PROGRAM Interlock
VAR
	TON_PG21: TON;
	TON_PG22: TOF;
	TON_PG23: TOF;
	MS11_S_TON: TON;
	MS2_S_TON: TON;
	MS12_S_TON: TON;
	BufferN2Press_TON: TON;
	VP1Down_TON: TON;
	DG1_TON: TON;
	OT_RHC_TON: TON;
	BlowerOverLoad_RTrig: R_TRIG;
	HTConc_RTrig: R_TRIG;
	T102Conc_RTrig: R_TRIG;
	
	VAC1_TON: TON;
	VAC1_Bypass: R_TRIG;
	bVAC1_Bypass: BOOL;
	VAC2_TON: TON;
	bVAC2_Bypass: BOOL;
	VAC2_Bypass: R_TRIG;
	VAC3_TON: TON;
	bVAC3_Bypass: BOOL;
	VAC3_Bypass: R_TRIG;
	VAC4_TON: TON;
	bVAC4_Bypass: BOOL;
	VAC4_Bypass: R_TRIG;
	VAC5_TON: TON;
	bVAC5_Bypass: BOOL;
	VAC5_Bypass: R_TRIG;
	AV73_TOF: TOF;
	T_REF_TON: TON;
	FL301_TON: TON;
	
	bRHC_Damper_Open			:BOOL;	// RHC Dapmer in open position
	bRHC_Damper_Close			:BOOL;	// RHC Damper in close position
	bMS2_MS2S_Status_Abnormal	:BOOL;	// MS2和MS2-S状态不一致
	bMS11_MS11S_Status_Abnormal	:BOOL;	// MS11和MS11-S状态不一致
	bMS12_MS12S_Status_Abnormal	:BOOL;	// MS12和MS12-S状态不一致
	bGV_Open					:BOOL;	// Gate valve open status
	bGV_Close					:BOOL;	// Gate valve close status
	bFFUAlarm					:BOOL;	// FFU alarm
	GV_Open_TON: TON;
	GV_Close_TON: TON;
	ATM_Dpr_Cl_TON: TON;
	ATM_Dpr_Op_TON: TON;
	Cycle_Dpr_Op_TON: TON;
	Cycle_Dpr_Cl_TON: TON;
	LSC_Float_Abnormal_TON: TON;
	LSC_HH_TON: TON;
	LSC_H_TON:TON;
	LSC_M_TON: TON;
	LSC_L_TON: TON;
	GasMS_Abnormal_TON :TON;
	T_REF_ET: TIME;
	AV73_ET: TIME;
	GV_Open_ET: TIME;
	GV_Close_ET: TIME;
	BufferN2Press_ET: TIME;
	LSC_Float_Abnormal_ET: TIME;
	TON_PG23_ET: TIME;
	LSC_HH_TON_ET: TIME;
	LSC_H_TON_ET: TIME;
	LSC_M_TON_ET: TIME;
	LSC_L_TON_ET: TIME;
	VP1Down_TON_ET: TIME;
	ATM_Dpr_Op_TON_ET: TIME;
	ATM_Dpr_Cl_TON_ET: TIME;
	Cycle_Dpr_Op_TON_ET: TIME;
	Cycle_Dpr_Cl_TON_ET: TIME;
	MS12_S_TON_ET: TIME;
	MS11_S_TON_ET: TIME;
	MS2_S_TON_ET: TIME;
	FL301_TON_ET: TIME;
	TON_PG22_TON: TIME;
	DG1_TON_ET: TIME;
	GasMS_Abnormal_TON_ET: TIME;
	TON_PG21_ET: TIME;
	OT_RHC_TON_ET: TIME;
	VAC4_TON_ET: TIME;
	VAC1_TON_ET: TIME;
	VAC5_TON_ET: TIME;
	VAC3_TON_ET: TIME;
	VAC2_TON_ET: TIME;
	PG23_TON: TON;
	PG22_TON: TON;
	RHC_Damper_Pos_TON: TON;
	RHC_Damper_Pos_TON_ET: TIME;
	LSC1_Refill_TON: TON;
	LSC1_H_Trig: R_TRIG;
	bLSC1_H_OK: BOOL;
	LSC1_Refill_TON_ET: TIME;
	PS21_TON: TON;
	PS21_TON_ET: TIME;
	VG11_Warning	: dut_UDINT_BOOL ;
	VG11_Error		: dut_UDINT_BOOL ;
	VG13_Warning	: dut_UDINT_BOOL ;
	VG13_Error		: dut_UDINT_BOOL ;
	VG31_Warning	: dut_UDINT_BOOL ;
	VG31_Error		: dut_UDINT_BOOL ;
END_VAR
VAR // added by the converter: edge detectors and wires of the graphical bodies
    _w1, _w2, _w3, _w4, _w5, _w6, _w7, _w8, _w9, _w10, _w11, _w12, _w13, _w14, _w15, _w16, _w17 : BOOL;
    _ft1 : F_TRIG;
END_VAR

//Interlock平时不触发为OFF，触发时为ON并发出报警相关阀无法打开，需要复位后才可进一步操作

INTLK();
Valve_Intlk();
AutoValve_Intlk();
VAC_Condition();
BoatUnload_Intlk();

bRHC_Damper_Open := stEXHI.I303_02 AND stEXHI.I303_04 AND stEXHI.I303_06 AND stEXHI.I303_08 ;
bRHC_Damper_Close:= stEXHI.I303_03 AND stEXHI.I303_05 AND stEXHI.I303_07 AND stEXHI.I303_09 ;

bMS2_MS2S_Status_Abnormal   := stGBI.I202_00 XOR GVL.stPMCtoPLC.MS2_S_gas_box_exhaust_alarm  ;
bMS11_MS11S_Status_Abnormal := stOPI.I600_10 XOR GVL.stPMCtoPLC.MS11_S_gas_box_exhaust_alarm ;
bMS12_MS12S_Status_Abnormal := stOPI.I600_12 XOR GVL.stPMCtoPLC.MS12_S_gas_box_exhaust_alarm ;

bGV_Open	:= stEXHI.I303_13 AND stEXHI.I303_15 ;
bGV_Close	:= stEXHI.I303_12 AND stEXHI.I303_14 ;

VG11_Warning.Data_UDINT := GVL.stPMCtoPLC.VG11_Active_Device_Warning_Details ;
VG11_Error.Data_UDINT	:= GVL.stPMCtoPLC.VG11_Active_Device_Error_Details	 ;

VG13_Warning.Data_UDINT := GVL.stPMCtoPLC.VG13_Active_Device_Warning_Details ;
VG13_Error.Data_UDINT	:= GVL.stPMCtoPLC.VG13_Active_Device_Error_Details	 ;

VG31_Warning.Data_UDINT := GVL.stPMCtoPLC.VG31_Active_Device_Warning_Details ;
VG31_Error.Data_UDINT	:= GVL.stPMCtoPLC.VG31_Active_Device_Error_Details	 ;

//FFU停转状态
bFFUAlarm := 
	( AI.FFU1_1_STATUS = 1 OR AI.FFU1_1_STATUS = 4 ) OR 
	( AI.FFU1_2_STATUS = 1 OR AI.FFU1_2_STATUS = 4 ) OR 
	( AI.FFU1_3_STATUS = 1 OR AI.FFU1_3_STATUS = 4 ) OR 
	( AI.FFU1_4_STATUS = 1 OR AI.FFU1_4_STATUS = 4 ) OR 
	( AI.FFU1_5_STATUS = 1 OR AI.FFU1_5_STATUS = 4 ) OR 
	( AI.FFU1_6_STATUS = 1 OR AI.FFU1_6_STATUS = 4 ) OR 
	( AI.FFU2_1_STATUS = 1 OR AI.FFU2_1_STATUS = 4 ) OR 
	( AI.FFU2_2_STATUS = 1 OR AI.FFU2_2_STATUS = 4 ) OR 
	( AI.FFU2_3_STATUS = 1 OR AI.FFU2_3_STATUS = 4 ) OR 
	( AI.FFU2_4_STATUS = 1 OR AI.FFU2_4_STATUS = 4 ) OR 
	( AI.FFU2_5_STATUS = 1 OR AI.FFU2_5_STATUS = 4 ) OR 
	( AI.FFU2_6_STATUS = 1 OR AI.FFU2_6_STATUS = 4 ) OR 
	( AI.FFU3_1_STATUS = 1 OR AI.FFU3_1_STATUS = 4 ) OR 
	( AI.FFU3_2_STATUS = 1 OR AI.FFU3_2_STATUS = 4 ) OR 
	( AI.FFU3_3_STATUS = 1 OR AI.FFU3_3_STATUS = 4 ) OR 
	( AI.FFU3_4_STATUS = 1 OR AI.FFU3_4_STATUS = 4 ) OR 
	( AI.FFU3_5_STATUS = 1 OR AI.FFU3_5_STATUS = 4 ) OR 
	( AI.FFU3_6_STATUS = 1 OR AI.FFU3_6_STATUS = 4 ) ;

ACTION AutoValve_Intlk:
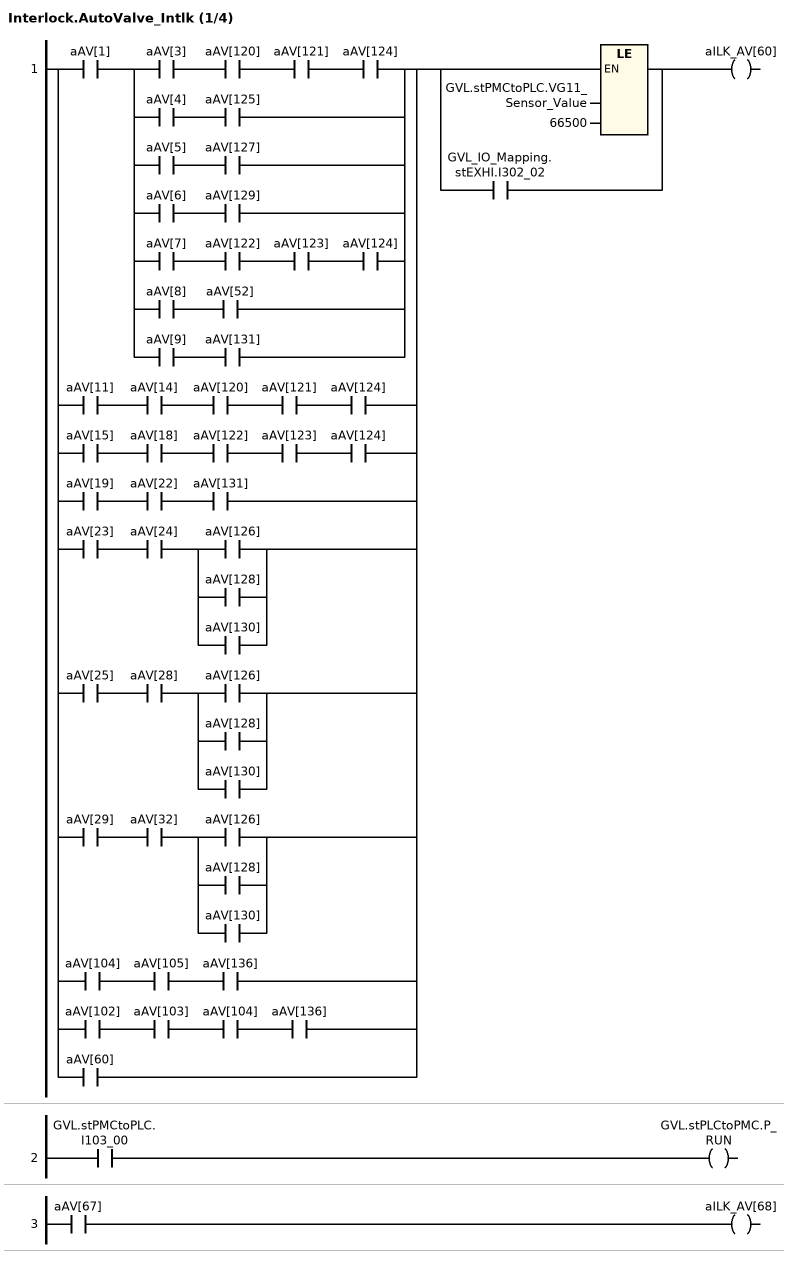
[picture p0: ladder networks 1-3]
// NETWORK 1
_w1 := aAV[1] AND (aAV[3] AND aAV[120] AND aAV[121] AND aAV[124] OR aAV[4] AND aAV[125] OR aAV[5] AND aAV[127] OR aAV[6] AND aAV[129] OR aAV[7] AND aAV[122] AND aAV[123] AND aAV[124] OR aAV[8] AND aAV[52] OR aAV[9] AND aAV[131]) OR aAV[11] AND aAV[14] AND aAV[120] AND aAV[121] AND aAV[124] OR aAV[15] AND aAV[18] AND aAV[122] AND aAV[123] AND aAV[124] OR aAV[19] AND aAV[22] AND aAV[131] OR aAV[23] AND aAV[24] AND (aAV[126] OR aAV[128] OR aAV[130]) OR aAV[25] AND aAV[28] AND (aAV[126] OR aAV[128] OR aAV[130]) OR aAV[29] AND aAV[32] AND (aAV[126] OR aAV[128] OR aAV[130]) OR aAV[104] AND aAV[105] AND aAV[136] OR aAV[102] AND aAV[103] AND aAV[104] AND aAV[136] OR aAV[60];
_w2 := _w1 AND GVL_IO_Mapping.stEXHI.I302_02;
IF NOT _w2 THEN
    _w2 := _w1 AND GVL.stPMCtoPLC.VG11_Sensor_Value <= 66500;
END_IF
aILK_AV[60] := _w2;

// NETWORK 2
GVL.stPLCtoPMC.P_RUN := GVL.stPMCtoPLC.I103_00;

// NETWORK 3
aILK_AV[68] := aAV[67];

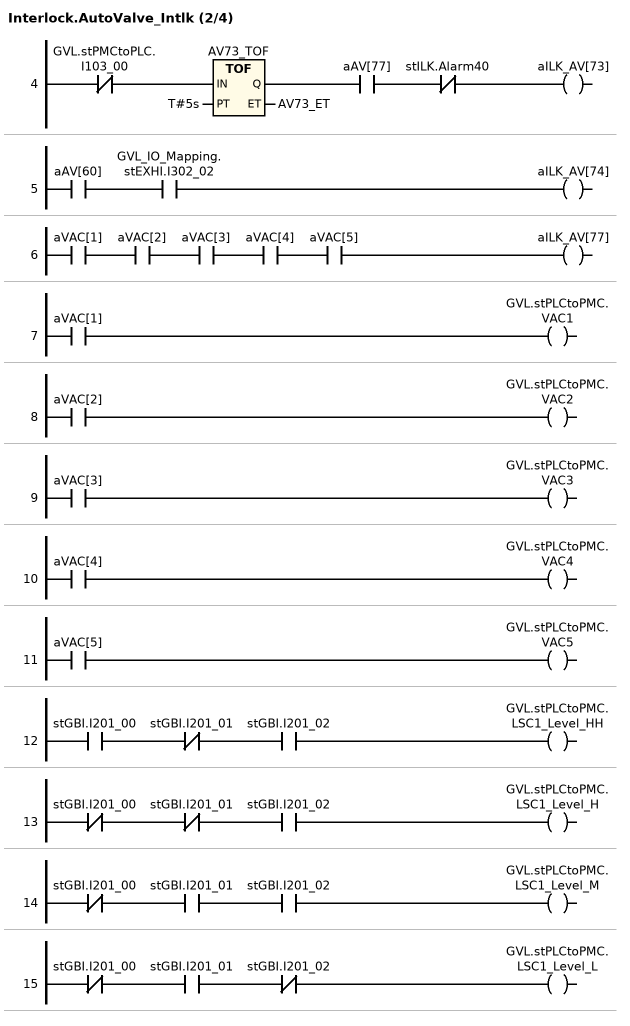
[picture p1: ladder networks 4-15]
// NETWORK 4
AV73_TOF(IN := NOT GVL.stPMCtoPLC.I103_00, PT := T#5s, ET => AV73_ET); // TOF
aILK_AV[73] := AV73_TOF.Q AND aAV[77] AND NOT stILK.Alarm40;

// NETWORK 5
aILK_AV[74] := aAV[60] AND GVL_IO_Mapping.stEXHI.I302_02;

// NETWORK 6
aILK_AV[77] := aVAC[1] AND aVAC[2] AND aVAC[3] AND aVAC[4] AND aVAC[5];

// NETWORK 7
GVL.stPLCtoPMC.VAC1 := aVAC[1];

// NETWORK 8
GVL.stPLCtoPMC.VAC2 := aVAC[2];

// NETWORK 9
GVL.stPLCtoPMC.VAC3 := aVAC[3];

// NETWORK 10
GVL.stPLCtoPMC.VAC4 := aVAC[4];

// NETWORK 11
GVL.stPLCtoPMC.VAC5 := aVAC[5];

// NETWORK 12
GVL.stPLCtoPMC.LSC1_Level_HH := stGBI.I201_00 AND NOT stGBI.I201_01 AND stGBI.I201_02;

// NETWORK 13
GVL.stPLCtoPMC.LSC1_Level_H := NOT stGBI.I201_00 AND NOT stGBI.I201_01 AND stGBI.I201_02;

// NETWORK 14
GVL.stPLCtoPMC.LSC1_Level_M := NOT stGBI.I201_00 AND stGBI.I201_01 AND stGBI.I201_02;

// NETWORK 15
GVL.stPLCtoPMC.LSC1_Level_L := NOT stGBI.I201_00 AND stGBI.I201_01 AND NOT stGBI.I201_02;

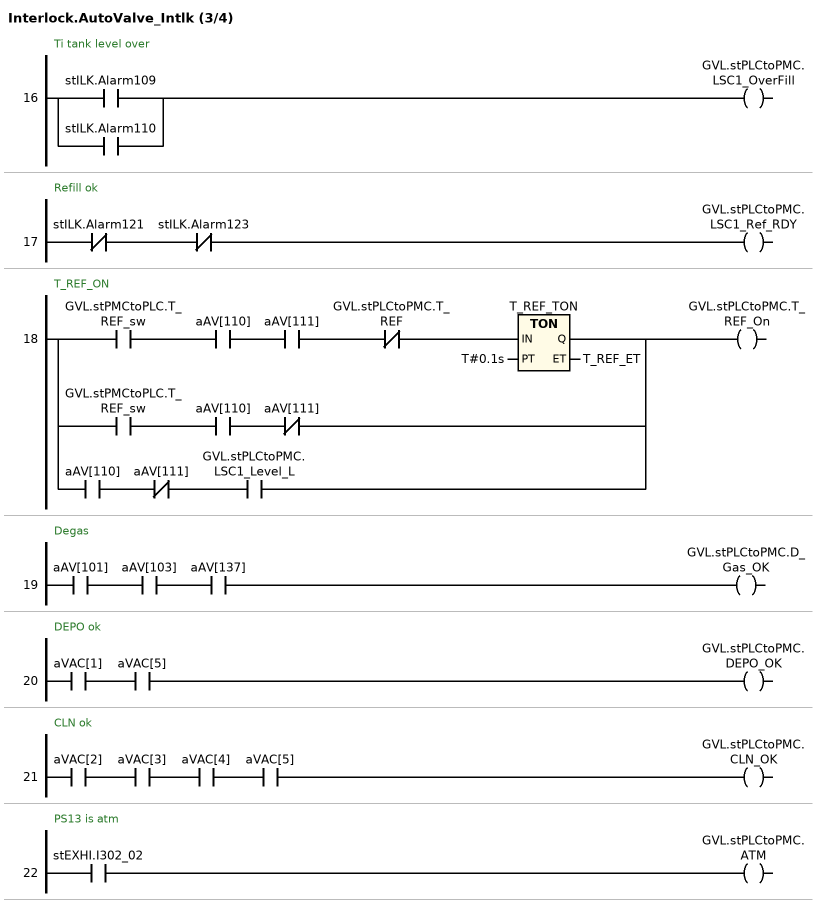
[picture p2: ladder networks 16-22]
// NETWORK 16
// Ti tank level over
GVL.stPLCtoPMC.LSC1_OverFill := stILK.Alarm109 OR stILK.Alarm110;

// NETWORK 17
// Refill ok
GVL.stPLCtoPMC.LSC1_Ref_RDY := NOT stILK.Alarm121 AND NOT stILK.Alarm123;

// NETWORK 18
// T_REF_ON
T_REF_TON(
    IN := GVL.stPMCtoPLC.T_REF_sw AND aAV[110] AND aAV[111] AND NOT GVL.stPLCtoPMC.T_REF,
    PT := T#0.1s,
    ET => T_REF_ET); // TON
GVL.stPLCtoPMC.T_REF_On := T_REF_TON.Q OR GVL.stPMCtoPLC.T_REF_sw AND aAV[110] AND NOT aAV[111] OR aAV[110] AND NOT aAV[111] AND GVL.stPLCtoPMC.LSC1_Level_L;

// NETWORK 19
// Degas
GVL.stPLCtoPMC.D_Gas_OK := aAV[101] AND aAV[103] AND aAV[137];

// NETWORK 20
// DEPO ok
GVL.stPLCtoPMC.DEPO_OK := aVAC[1] AND aVAC[5];

// NETWORK 21
// CLN ok
GVL.stPLCtoPMC.CLN_OK := aVAC[2] AND aVAC[3] AND aVAC[4] AND aVAC[5];

// NETWORK 22
// PS13 is atm
GVL.stPLCtoPMC.ATM := stEXHI.I302_02;

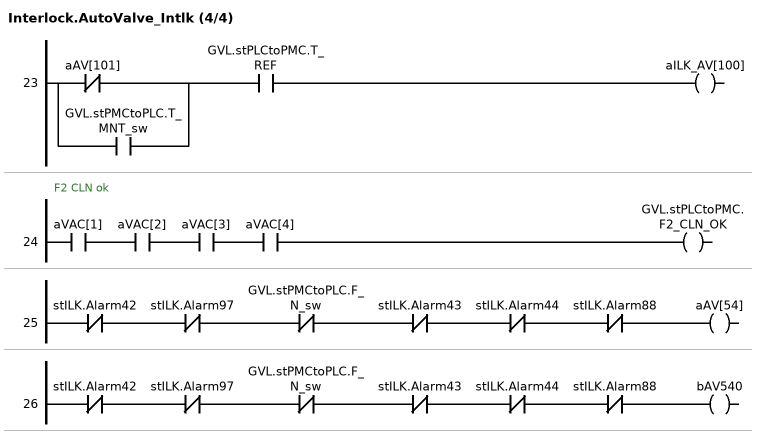
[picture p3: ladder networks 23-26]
// NETWORK 23
aILK_AV[100] := (NOT aAV[101] OR GVL.stPMCtoPLC.T_MNT_sw) AND GVL.stPLCtoPMC.T_REF;

// NETWORK 24
// F2 CLN ok
GVL.stPLCtoPMC.F2_CLN_OK := aVAC[1] AND aVAC[2] AND aVAC[3] AND aVAC[4];

// NETWORK 25
aAV[54] := NOT stILK.Alarm42 AND NOT stILK.Alarm97 AND NOT GVL.stPMCtoPLC.F_N_sw AND NOT stILK.Alarm43 AND NOT stILK.Alarm44 AND NOT stILK.Alarm88;

// NETWORK 26
bAV540 := NOT stILK.Alarm42 AND NOT stILK.Alarm97 AND NOT GVL.stPMCtoPLC.F_N_sw AND NOT stILK.Alarm43 AND NOT stILK.Alarm44 AND NOT stILK.Alarm88;
END_ACTION

ACTION BoatUnload_Intlk:
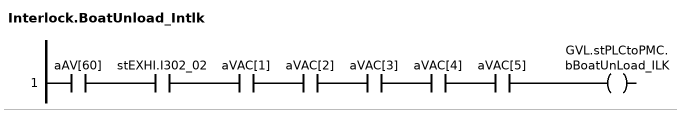
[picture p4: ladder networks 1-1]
// NETWORK 1
GVL.stPLCtoPMC.bBoatUnLoad_ILK := aAV[60] AND stEXHI.I302_02 AND aVAC[1] AND aVAC[2] AND aVAC[3] AND aVAC[4] AND aVAC[5];
END_ACTION

ACTION Intlk:
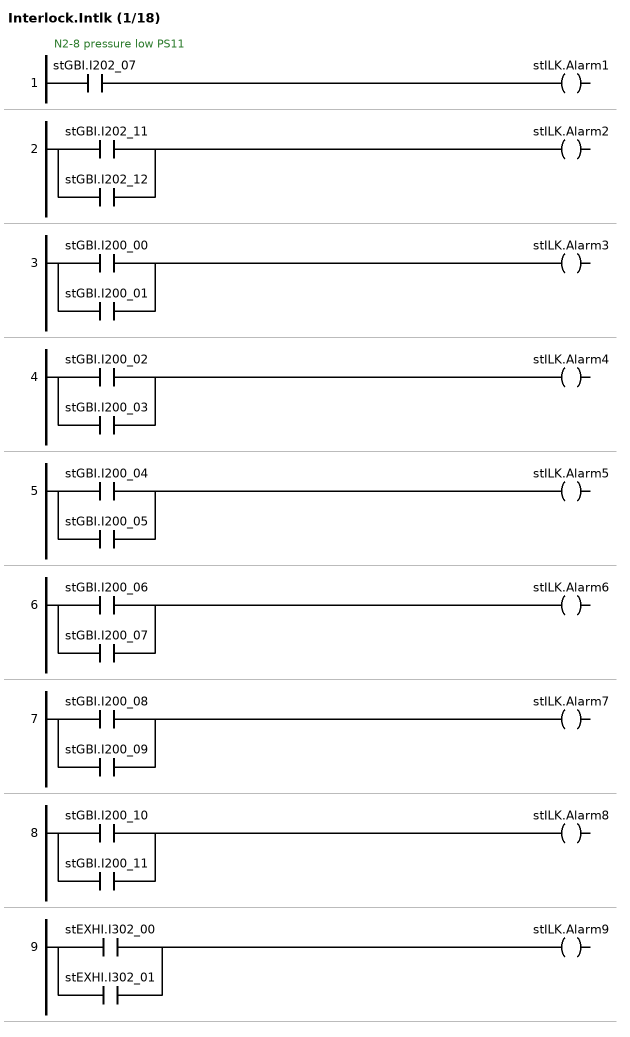
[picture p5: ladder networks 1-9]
// NETWORK 1
// N2-8 pressure low PS11
stILK.Alarm1 := stGBI.I202_07;

// NETWORK 2
stILK.Alarm2 := stGBI.I202_11 OR stGBI.I202_12;

// NETWORK 3
stILK.Alarm3 := stGBI.I200_00 OR stGBI.I200_01;

// NETWORK 4
stILK.Alarm4 := stGBI.I200_02 OR stGBI.I200_03;

// NETWORK 5
stILK.Alarm5 := stGBI.I200_04 OR stGBI.I200_05;

// NETWORK 6
stILK.Alarm6 := stGBI.I200_06 OR stGBI.I200_07;

// NETWORK 7
stILK.Alarm7 := stGBI.I200_08 OR stGBI.I200_09;

// NETWORK 8
stILK.Alarm8 := stGBI.I200_10 OR stGBI.I200_11;

// NETWORK 9
stILK.Alarm9 := stEXHI.I302_00 OR stEXHI.I302_01;

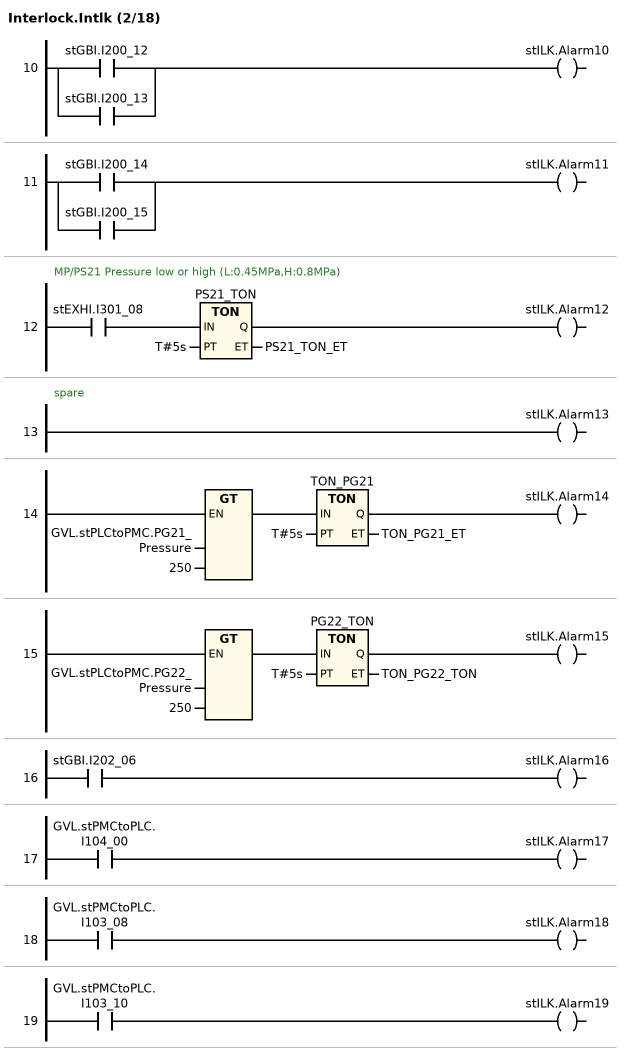
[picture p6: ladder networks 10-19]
// NETWORK 10
stILK.Alarm10 := stGBI.I200_12 OR stGBI.I200_13;

// NETWORK 11
stILK.Alarm11 := stGBI.I200_14 OR stGBI.I200_15;

// NETWORK 12
// MP/PS21 Pressure low or high (L:0.45MPa,H:0.8MPa)
PS21_TON(IN := stEXHI.I301_08, PT := T#5s, ET => PS21_TON_ET); // TON
stILK.Alarm12 := PS21_TON.Q;

// NETWORK 13
// spare
stILK.Alarm13 := TRUE;

// NETWORK 14
TON_PG21(IN := GVL.stPLCtoPMC.PG21_Pressure > 250, PT := T#5s, ET => TON_PG21_ET); // TON
stILK.Alarm14 := TON_PG21.Q;

// NETWORK 15
PG22_TON(IN := GVL.stPLCtoPMC.PG22_Pressure > 250, PT := T#5s, ET => TON_PG22_TON); // TON
stILK.Alarm15 := PG22_TON.Q;

// NETWORK 16
stILK.Alarm16 := stGBI.I202_06;

// NETWORK 17
stILK.Alarm17 := GVL.stPMCtoPLC.I104_00;

// NETWORK 18
stILK.Alarm18 := GVL.stPMCtoPLC.I103_08;

// NETWORK 19
stILK.Alarm19 := GVL.stPMCtoPLC.I103_10;

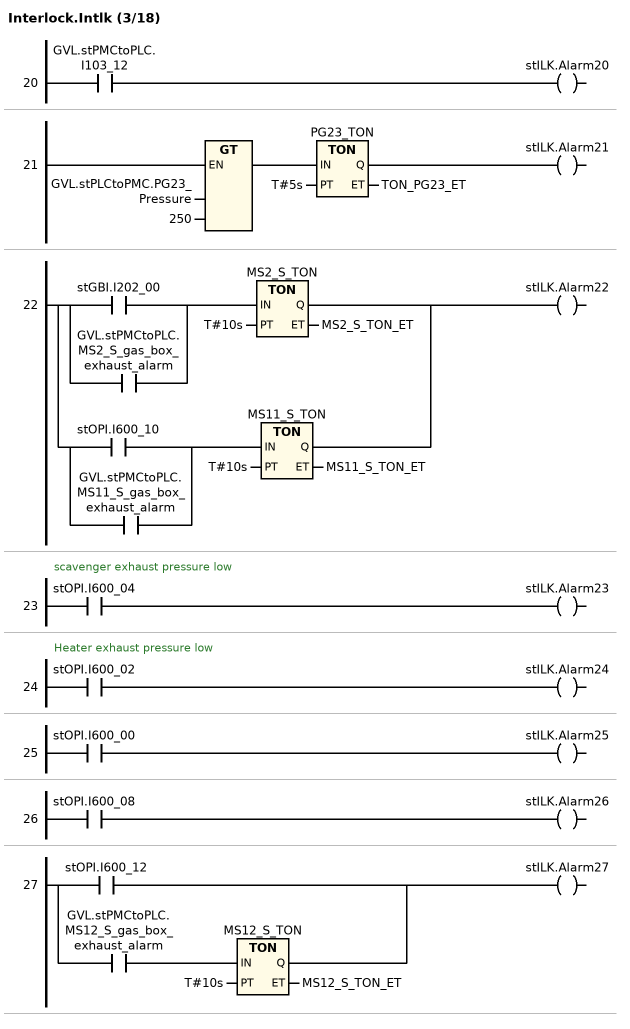
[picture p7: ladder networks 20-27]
// NETWORK 20
stILK.Alarm20 := GVL.stPMCtoPLC.I103_12;

// NETWORK 21
PG23_TON(IN := GVL.stPLCtoPMC.PG23_Pressure > 250, PT := T#5s, ET => TON_PG23_ET); // TON
stILK.Alarm21 := PG23_TON.Q;

// NETWORK 22
MS2_S_TON(IN := stGBI.I202_00 OR GVL.stPMCtoPLC.MS2_S_gas_box_exhaust_alarm, PT := T#10s, ET => MS2_S_TON_ET); // TON
MS11_S_TON(
    IN := stOPI.I600_10 OR GVL.stPMCtoPLC.MS11_S_gas_box_exhaust_alarm,
    PT := T#10s,
    ET => MS11_S_TON_ET); // TON
stILK.Alarm22 := MS2_S_TON.Q OR MS11_S_TON.Q;

// NETWORK 23
// scavenger exhaust pressure low
stILK.Alarm23 := stOPI.I600_04;

// NETWORK 24
// Heater exhaust pressure low
stILK.Alarm24 := stOPI.I600_02;

// NETWORK 25
stILK.Alarm25 := stOPI.I600_00;

// NETWORK 26
stILK.Alarm26 := stOPI.I600_08;

// NETWORK 27
MS12_S_TON(IN := GVL.stPMCtoPLC.MS12_S_gas_box_exhaust_alarm, PT := T#10s, ET => MS12_S_TON_ET); // TON
stILK.Alarm27 := stOPI.I600_12 OR MS12_S_TON.Q;

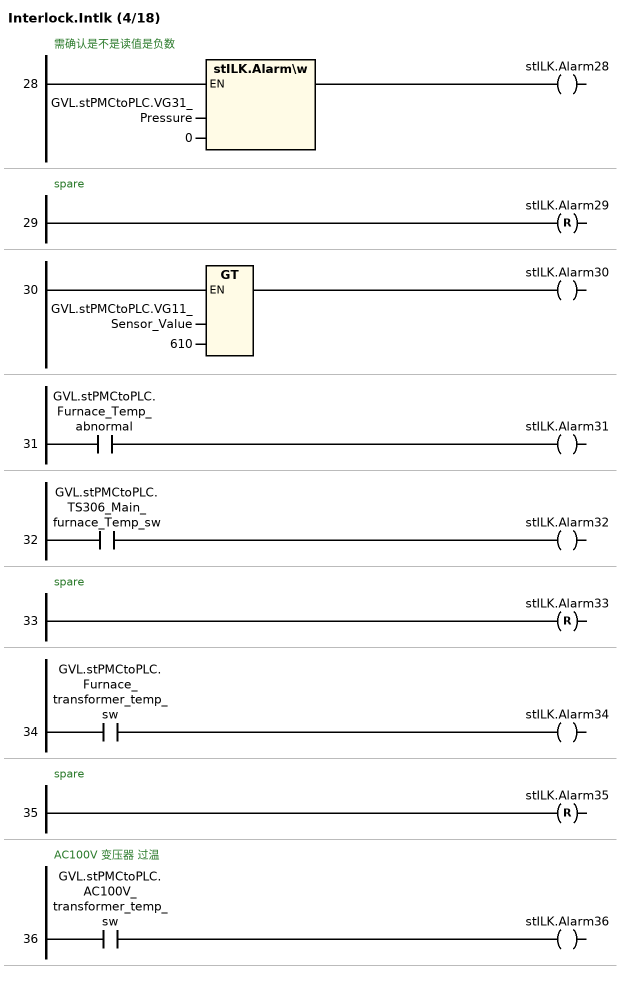
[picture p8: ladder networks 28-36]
// NETWORK 28
// 需确认是不是读值是负数
stILK.Alarm28 := stILK.Alarm\w(GVL.stPMCtoPLC.VG31_Pressure, 0);

// NETWORK 29
// spare
stILK.Alarm29 R= TRUE;

// NETWORK 30
stILK.Alarm30 := GVL.stPMCtoPLC.VG11_Sensor_Value > 610;

// NETWORK 31
stILK.Alarm31 := GVL.stPMCtoPLC.Furnace_Temp_abnormal;

// NETWORK 32
stILK.Alarm32 := GVL.stPMCtoPLC.TS306_Main_furnace_Temp_sw;

// NETWORK 33
// spare
stILK.Alarm33 R= TRUE;

// NETWORK 34
stILK.Alarm34 := GVL.stPMCtoPLC.Furnace_transformer_temp_sw;

// NETWORK 35
// spare
stILK.Alarm35 R= TRUE;

// NETWORK 36
// AC100V 变压器 过温
stILK.Alarm36 := GVL.stPMCtoPLC.AC100V_transformer_temp_sw;

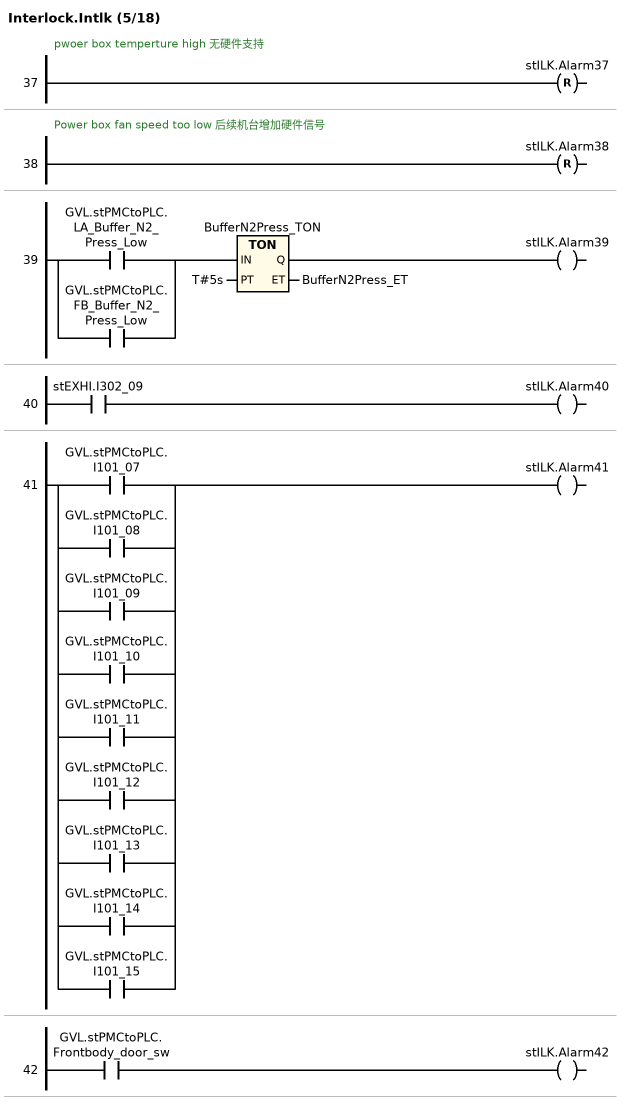
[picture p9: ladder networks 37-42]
// NETWORK 37
// pwoer box temperture high 无硬件支持
stILK.Alarm37 R= TRUE;

// NETWORK 38
// Power box fan speed too low 后续机台增加硬件信号
stILK.Alarm38 R= TRUE;

// NETWORK 39
BufferN2Press_TON(
    IN := GVL.stPMCtoPLC.LA_Buffer_N2_Press_Low OR GVL.stPMCtoPLC.FB_Buffer_N2_Press_Low,
    PT := T#5s,
    ET => BufferN2Press_ET); // TON
stILK.Alarm39 := BufferN2Press_TON.Q;

// NETWORK 40
stILK.Alarm40 := stEXHI.I302_09;

// NETWORK 41
stILK.Alarm41 := GVL.stPMCtoPLC.I101_07 OR GVL.stPMCtoPLC.I101_08 OR GVL.stPMCtoPLC.I101_09 OR GVL.stPMCtoPLC.I101_10 OR GVL.stPMCtoPLC.I101_11 OR GVL.stPMCtoPLC.I101_12 OR GVL.stPMCtoPLC.I101_13 OR GVL.stPMCtoPLC.I101_14 OR GVL.stPMCtoPLC.I101_15;

// NETWORK 42
stILK.Alarm42 := GVL.stPMCtoPLC.Frontbody_door_sw;

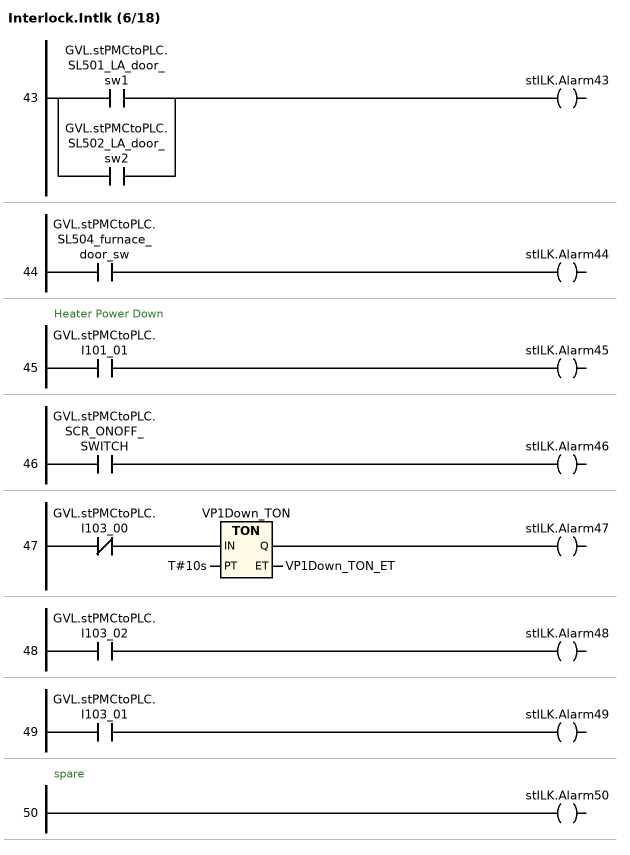
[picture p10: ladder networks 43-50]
// NETWORK 43
stILK.Alarm43 := GVL.stPMCtoPLC.SL501_LA_door_sw1 OR GVL.stPMCtoPLC.SL502_LA_door_sw2;

// NETWORK 44
stILK.Alarm44 := GVL.stPMCtoPLC.SL504_furnace_door_sw;

// NETWORK 45
// Heater Power Down
stILK.Alarm45 := GVL.stPMCtoPLC.I101_01;

// NETWORK 46
stILK.Alarm46 := GVL.stPMCtoPLC.SCR_ONOFF_SWITCH;

// NETWORK 47
VP1Down_TON(IN := NOT GVL.stPMCtoPLC.I103_00, PT := T#10s, ET => VP1Down_TON_ET); // TON
stILK.Alarm47 := VP1Down_TON.Q;

// NETWORK 48
stILK.Alarm48 := GVL.stPMCtoPLC.I103_02;

// NETWORK 49
stILK.Alarm49 := GVL.stPMCtoPLC.I103_01;

// NETWORK 50
// spare
stILK.Alarm50 := TRUE;

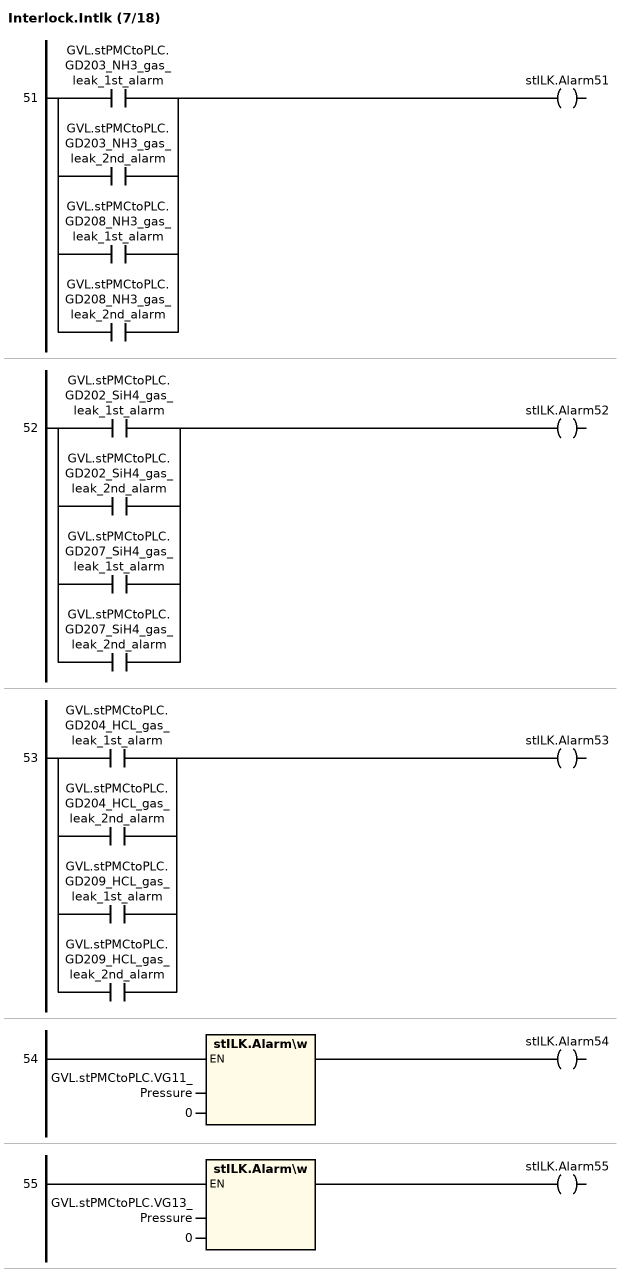
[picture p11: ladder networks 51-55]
// NETWORK 51
stILK.Alarm51 := GVL.stPMCtoPLC.GD203_NH3_gas_leak_1st_alarm OR GVL.stPMCtoPLC.GD203_NH3_gas_leak_2nd_alarm OR GVL.stPMCtoPLC.GD208_NH3_gas_leak_1st_alarm OR GVL.stPMCtoPLC.GD208_NH3_gas_leak_2nd_alarm;

// NETWORK 52
stILK.Alarm52 := GVL.stPMCtoPLC.GD202_SiH4_gas_leak_1st_alarm OR GVL.stPMCtoPLC.GD202_SiH4_gas_leak_2nd_alarm OR GVL.stPMCtoPLC.GD207_SiH4_gas_leak_1st_alarm OR GVL.stPMCtoPLC.GD207_SiH4_gas_leak_2nd_alarm;

// NETWORK 53
stILK.Alarm53 := GVL.stPMCtoPLC.GD204_HCL_gas_leak_1st_alarm OR GVL.stPMCtoPLC.GD204_HCL_gas_leak_2nd_alarm OR GVL.stPMCtoPLC.GD209_HCL_gas_leak_1st_alarm OR GVL.stPMCtoPLC.GD209_HCL_gas_leak_2nd_alarm;

// NETWORK 54
stILK.Alarm54 := stILK.Alarm\w(GVL.stPMCtoPLC.VG11_Pressure, 0);

// NETWORK 55
stILK.Alarm55 := stILK.Alarm\w(GVL.stPMCtoPLC.VG13_Pressure, 0);

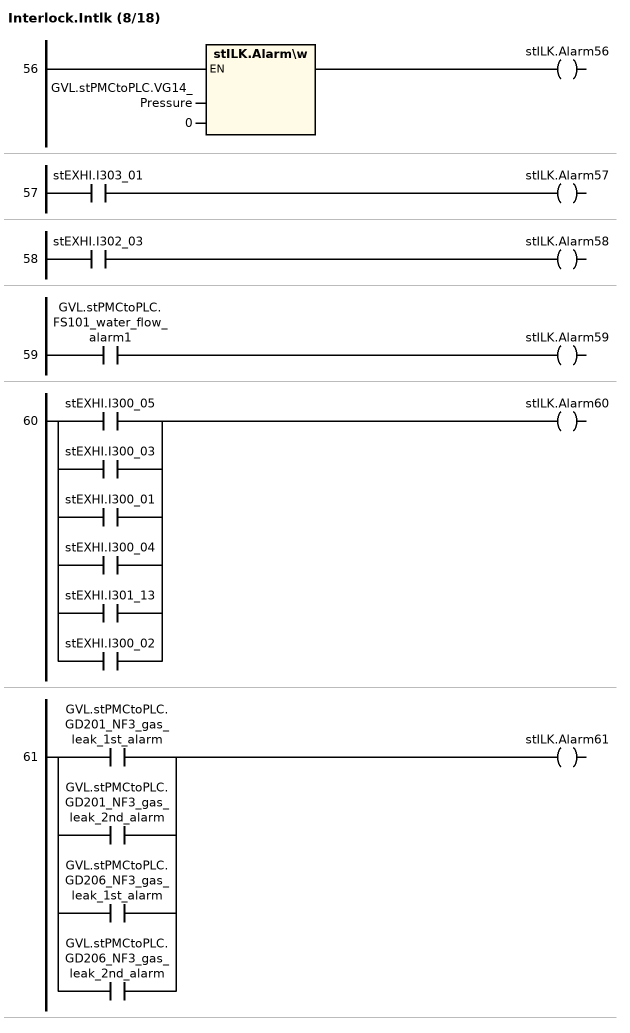
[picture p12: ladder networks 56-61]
// NETWORK 56
stILK.Alarm56 := stILK.Alarm\w(GVL.stPMCtoPLC.VG14_Pressure, 0);

// NETWORK 57
stILK.Alarm57 := stEXHI.I303_01;

// NETWORK 58
stILK.Alarm58 := stEXHI.I302_03;

// NETWORK 59
stILK.Alarm59 := GVL.stPMCtoPLC.FS101_water_flow_alarm1;

// NETWORK 60
stILK.Alarm60 := stEXHI.I300_05 OR stEXHI.I300_03 OR stEXHI.I300_01 OR stEXHI.I300_04 OR stEXHI.I301_13 OR stEXHI.I300_02;

// NETWORK 61
stILK.Alarm61 := GVL.stPMCtoPLC.GD201_NF3_gas_leak_1st_alarm OR GVL.stPMCtoPLC.GD201_NF3_gas_leak_2nd_alarm OR GVL.stPMCtoPLC.GD206_NF3_gas_leak_1st_alarm OR GVL.stPMCtoPLC.GD206_NF3_gas_leak_2nd_alarm;

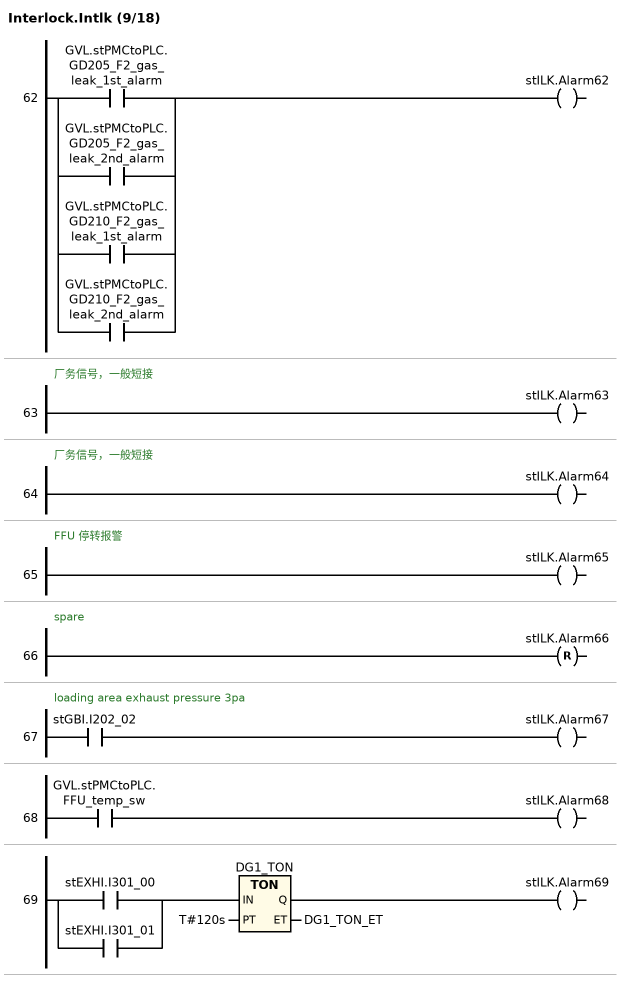
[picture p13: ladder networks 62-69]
// NETWORK 62
stILK.Alarm62 := GVL.stPMCtoPLC.GD205_F2_gas_leak_1st_alarm OR GVL.stPMCtoPLC.GD205_F2_gas_leak_2nd_alarm OR GVL.stPMCtoPLC.GD210_F2_gas_leak_1st_alarm OR GVL.stPMCtoPLC.GD210_F2_gas_leak_2nd_alarm;

// NETWORK 63
// 厂务信号，一般短接
stILK.Alarm63 := TRUE;

// NETWORK 64
// 厂务信号，一般短接
stILK.Alarm64 := TRUE;

// NETWORK 65
// FFU 停转报警
stILK.Alarm65 := TRUE;

// NETWORK 66
// spare
stILK.Alarm66 R= TRUE;

// NETWORK 67
// loading area exhaust pressure 3pa
stILK.Alarm67 := stGBI.I202_02;

// NETWORK 68
stILK.Alarm68 := GVL.stPMCtoPLC.FFU_temp_sw;

// NETWORK 69
DG1_TON(IN := stEXHI.I301_00 OR stEXHI.I301_01, PT := T#120s, ET => DG1_TON_ET); // TON
stILK.Alarm69 := DG1_TON.Q;

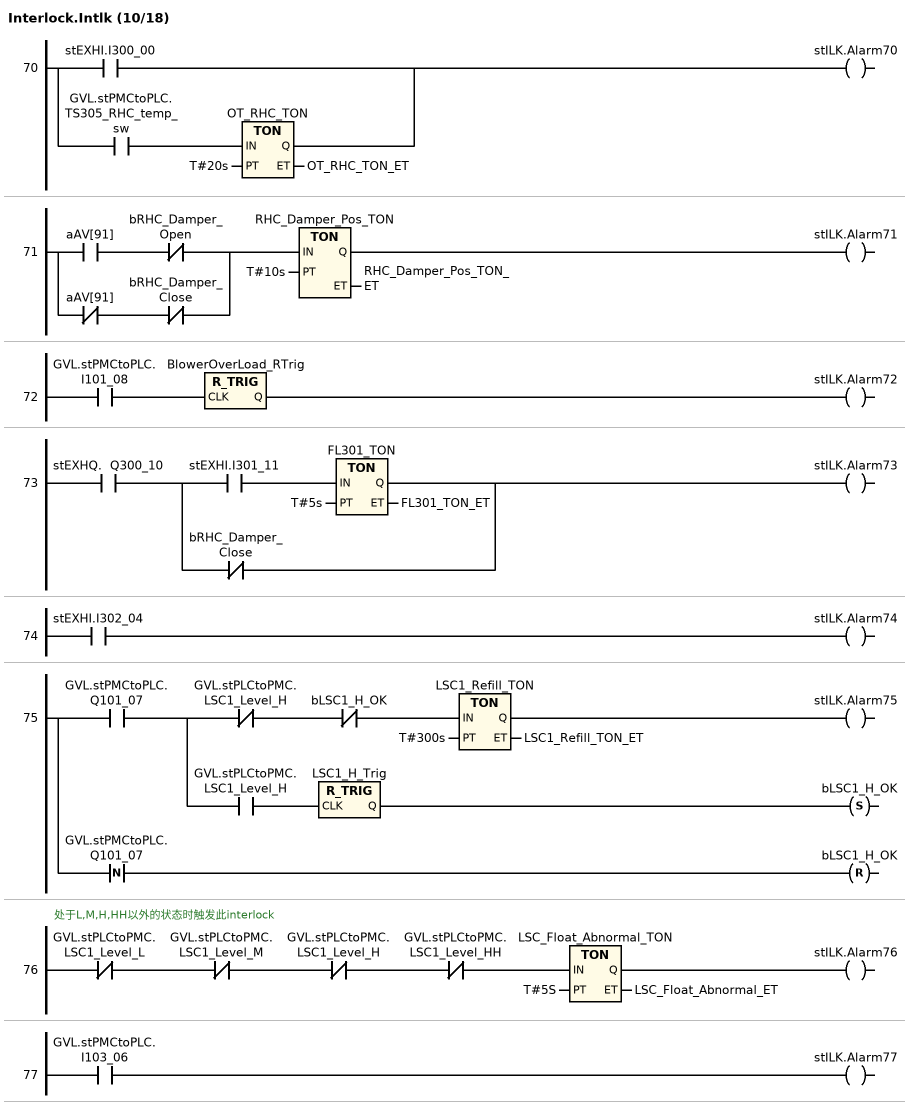
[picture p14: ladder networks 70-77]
// NETWORK 70
OT_RHC_TON(IN := GVL.stPMCtoPLC.TS305_RHC_temp_sw, PT := T#20s, ET => OT_RHC_TON_ET); // TON
stILK.Alarm70 := stEXHI.I300_00 OR OT_RHC_TON.Q;

// NETWORK 71
RHC_Damper_Pos_TON(
    IN := aAV[91] AND NOT bRHC_Damper_Open OR NOT aAV[91] AND NOT bRHC_Damper_Close,
    PT := T#10s,
    ET => RHC_Damper_Pos_TON_ET); // TON
stILK.Alarm71 := RHC_Damper_Pos_TON.Q;

// NETWORK 72
BlowerOverLoad_RTrig(CLK := GVL.stPMCtoPLC.I101_08); // R_TRIG
stILK.Alarm72 := BlowerOverLoad_RTrig.Q;

// NETWORK 73
_w3 := stEXHQ.	Q300_10;
_w4 := _w3 AND NOT bRHC_Damper_Close;
IF NOT _w4 THEN
    FL301_TON(IN := _w3 AND stEXHI.I301_11, PT := T#5s, ET => FL301_TON_ET); // TON
    _w4 := FL301_TON.Q;
END_IF
stILK.Alarm73 := _w4;

// NETWORK 74
stILK.Alarm74 := stEXHI.I302_04;

// NETWORK 75
LSC1_Refill_TON(
    IN := GVL.stPMCtoPLC.Q101_07 AND NOT GVL.stPLCtoPMC.LSC1_Level_H AND NOT bLSC1_H_OK,
    PT := T#300s,
    ET => LSC1_Refill_TON_ET); // TON
stILK.Alarm75 := LSC1_Refill_TON.Q;
LSC1_H_Trig(CLK := GVL.stPMCtoPLC.Q101_07 AND GVL.stPLCtoPMC.LSC1_Level_H); // R_TRIG
bLSC1_H_OK S= LSC1_H_Trig.Q;
_ft1(CLK := GVL.stPMCtoPLC.Q101_07);
bLSC1_H_OK R= _ft1.Q;

// NETWORK 76
// 处于L,M,H,HH以外的状态时触发此interlock
LSC_Float_Abnormal_TON(
    IN := NOT GVL.stPLCtoPMC.LSC1_Level_L AND NOT GVL.stPLCtoPMC.LSC1_Level_M AND NOT GVL.stPLCtoPMC.LSC1_Level_H AND NOT GVL.stPLCtoPMC.LSC1_Level_HH,
    PT := T#5S,
    ET => LSC_Float_Abnormal_ET); // TON
stILK.Alarm76 := LSC_Float_Abnormal_TON.Q;

// NETWORK 77
stILK.Alarm77 := GVL.stPMCtoPLC.I103_06;

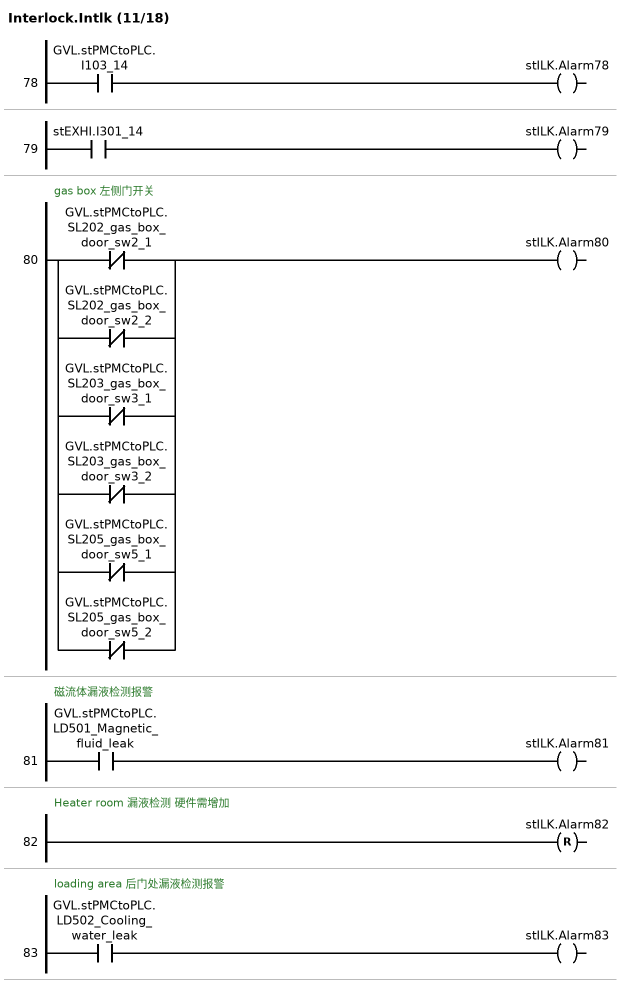
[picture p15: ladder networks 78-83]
// NETWORK 78
stILK.Alarm78 := GVL.stPMCtoPLC.I103_14;

// NETWORK 79
stILK.Alarm79 := stEXHI.I301_14;

// NETWORK 80
// gas box 左侧门开关
stILK.Alarm80 := NOT GVL.stPMCtoPLC.SL202_gas_box_door_sw2_1 OR NOT GVL.stPMCtoPLC.SL202_gas_box_door_sw2_2 OR NOT GVL.stPMCtoPLC.SL203_gas_box_door_sw3_1 OR NOT GVL.stPMCtoPLC.SL203_gas_box_door_sw3_2 OR NOT GVL.stPMCtoPLC.SL205_gas_box_door_sw5_1 OR NOT GVL.stPMCtoPLC.SL205_gas_box_door_sw5_2;

// NETWORK 81
// 磁流体漏液检测报警
stILK.Alarm81 := GVL.stPMCtoPLC.LD501_Magnetic_fluid_leak;

// NETWORK 82
// Heater room 漏液检测 硬件需增加
stILK.Alarm82 R= TRUE;

// NETWORK 83
// loading area 后门处漏液检测报警
stILK.Alarm83 := GVL.stPMCtoPLC.LD502_Cooling_water_leak;

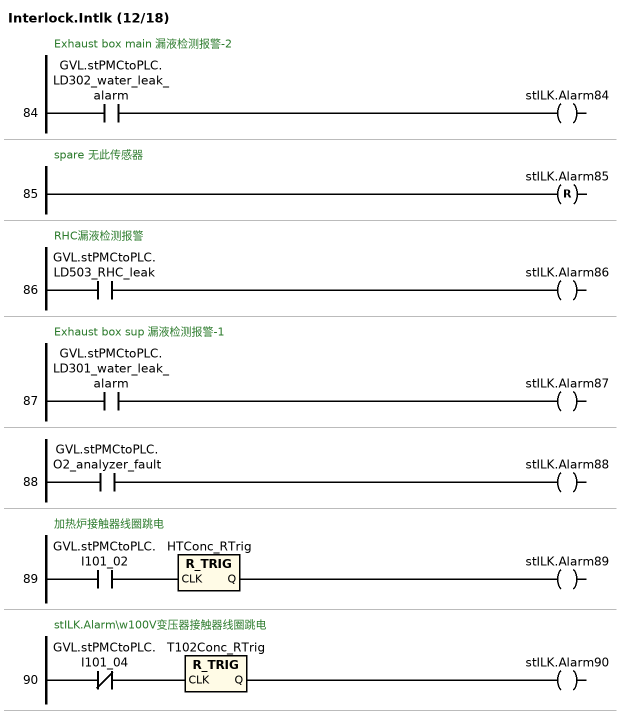
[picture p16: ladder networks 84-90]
// NETWORK 84
// Exhaust box main 漏液检测报警-2
stILK.Alarm84 := GVL.stPMCtoPLC.LD302_water_leak_alarm;

// NETWORK 85
// spare 无此传感器
stILK.Alarm85 R= TRUE;

// NETWORK 86
// RHC漏液检测报警
stILK.Alarm86 := GVL.stPMCtoPLC.LD503_RHC_leak;

// NETWORK 87
// Exhaust box sup 漏液检测报警-1
stILK.Alarm87 := GVL.stPMCtoPLC.LD301_water_leak_alarm;

// NETWORK 88
stILK.Alarm88 := GVL.stPMCtoPLC.O2_analyzer_fault;

// NETWORK 89
// 加热炉接触器线圈跳电
HTConc_RTrig(CLK := GVL.stPMCtoPLC.I101_02); // R_TRIG
stILK.Alarm89 := HTConc_RTrig.Q;

// NETWORK 90
// stILK.Alarm\w100V变压器接触器线圈跳电
T102Conc_RTrig(CLK := NOT GVL.stPMCtoPLC.I101_04); // R_TRIG
stILK.Alarm90 := T102Conc_RTrig.Q;

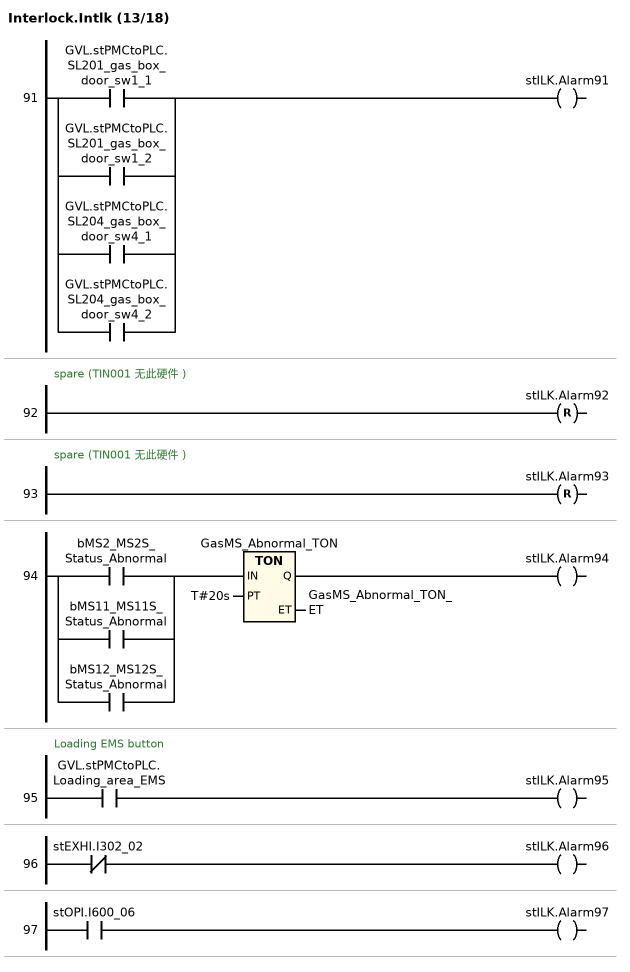
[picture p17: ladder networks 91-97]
// NETWORK 91
stILK.Alarm91 := GVL.stPMCtoPLC.SL201_gas_box_door_sw1_1 OR GVL.stPMCtoPLC.SL201_gas_box_door_sw1_2 OR GVL.stPMCtoPLC.SL204_gas_box_door_sw4_1 OR GVL.stPMCtoPLC.SL204_gas_box_door_sw4_2;

// NETWORK 92
// spare (TIN001 无此硬件 )
stILK.Alarm92 R= TRUE;

// NETWORK 93
// spare (TIN001 无此硬件 )
stILK.Alarm93 R= TRUE;

// NETWORK 94
GasMS_Abnormal_TON(
    IN := bMS2_MS2S_Status_Abnormal OR bMS11_MS11S_Status_Abnormal OR bMS12_MS12S_Status_Abnormal,
    PT := T#20s,
    ET => GasMS_Abnormal_TON_ET); // TON
stILK.Alarm94 := GasMS_Abnormal_TON.Q;

// NETWORK 95
// Loading EMS button
stILK.Alarm95 := GVL.stPMCtoPLC.Loading_area_EMS;

// NETWORK 96
stILK.Alarm96 := NOT stEXHI.I302_02;

// NETWORK 97
stILK.Alarm97 := stOPI.I600_06;

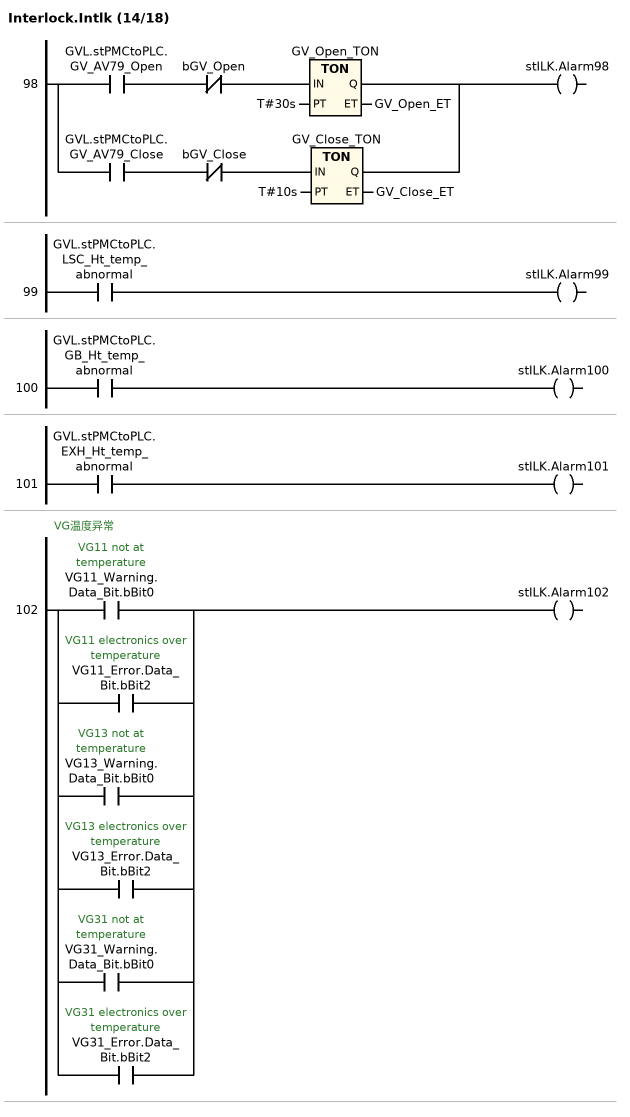
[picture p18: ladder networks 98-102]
// NETWORK 98
GV_Open_TON(IN := GVL.stPMCtoPLC.GV_AV79_Open AND NOT bGV_Open, PT := T#30s, ET => GV_Open_ET); // TON
GV_Close_TON(IN := GVL.stPMCtoPLC.GV_AV79_Close AND NOT bGV_Close, PT := T#10s, ET => GV_Close_ET); // TON
stILK.Alarm98 := GV_Open_TON.Q OR GV_Close_TON.Q;

// NETWORK 99
stILK.Alarm99 := GVL.stPMCtoPLC.LSC_Ht_temp_abnormal;

// NETWORK 100
stILK.Alarm100 := GVL.stPMCtoPLC.GB_Ht_temp_abnormal;

// NETWORK 101
stILK.Alarm101 := GVL.stPMCtoPLC.EXH_Ht_temp_abnormal;

// NETWORK 102
// VG温度异常
//   VG11_Warning.Data_Bit.bBit0: VG11 not at temperature
//   VG11_Error.Data_Bit.bBit2: VG11 electronics over temperature
//   VG13_Warning.Data_Bit.bBit0: VG13 not at temperature
//   VG13_Error.Data_Bit.bBit2: VG13 electronics over temperature
//   VG31_Warning.Data_Bit.bBit0: VG31 not at temperature
//   VG31_Error.Data_Bit.bBit2: VG31 electronics over temperature
stILK.Alarm102 := VG11_Warning.Data_Bit.bBit0 OR VG11_Error.Data_Bit.bBit2 OR VG13_Warning.Data_Bit.bBit0 OR VG13_Error.Data_Bit.bBit2 OR VG31_Warning.Data_Bit.bBit0 OR VG31_Error.Data_Bit.bBit2;

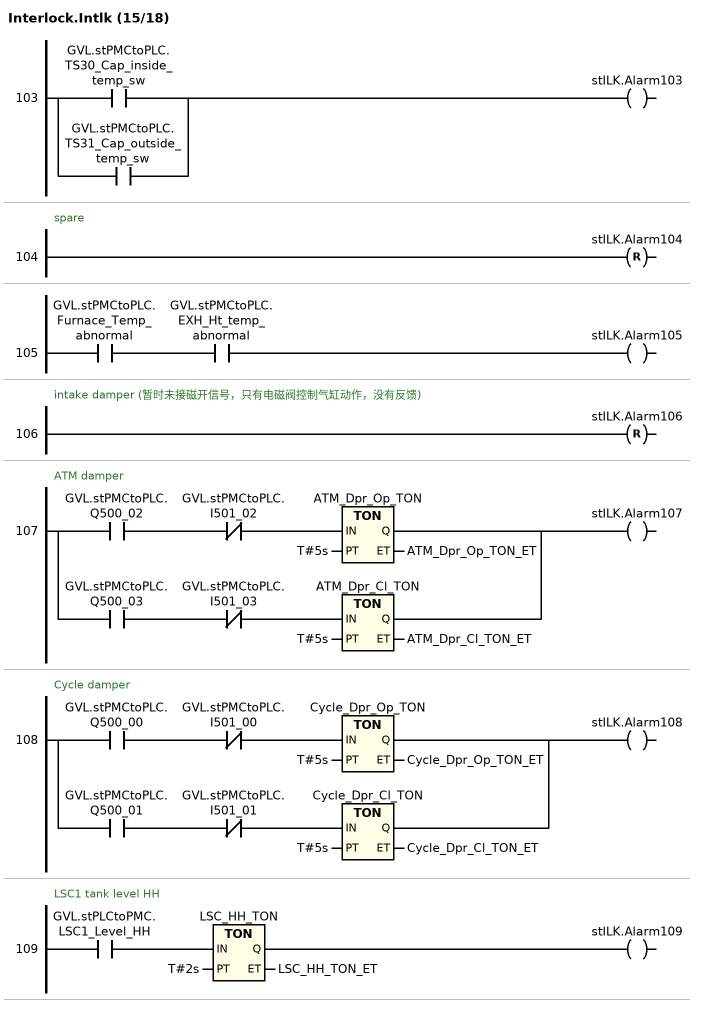
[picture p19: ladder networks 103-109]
// NETWORK 103
stILK.Alarm103 := GVL.stPMCtoPLC.TS30_Cap_inside_temp_sw OR GVL.stPMCtoPLC.TS31_Cap_outside_temp_sw;

// NETWORK 104
// spare
stILK.Alarm104 R= TRUE;

// NETWORK 105
stILK.Alarm105 := GVL.stPMCtoPLC.Furnace_Temp_abnormal AND GVL.stPMCtoPLC.EXH_Ht_temp_abnormal;

// NETWORK 106
// intake damper (暂时未接磁开信号，只有电磁阀控制气缸动作，没有反馈)
stILK.Alarm106 R= TRUE;

// NETWORK 107
// ATM damper
ATM_Dpr_Op_TON(
    IN := GVL.stPMCtoPLC.Q500_02 AND NOT GVL.stPMCtoPLC.I501_02,
    PT := T#5s,
    ET => ATM_Dpr_Op_TON_ET); // TON
ATM_Dpr_Cl_TON(
    IN := GVL.stPMCtoPLC.Q500_03 AND NOT GVL.stPMCtoPLC.I501_03,
    PT := T#5s,
    ET => ATM_Dpr_Cl_TON_ET); // TON
stILK.Alarm107 := ATM_Dpr_Op_TON.Q OR ATM_Dpr_Cl_TON.Q;

// NETWORK 108
// Cycle damper
Cycle_Dpr_Op_TON(
    IN := GVL.stPMCtoPLC.Q500_00 AND NOT GVL.stPMCtoPLC.I501_00,
    PT := T#5s,
    ET => Cycle_Dpr_Op_TON_ET); // TON
Cycle_Dpr_Cl_TON(
    IN := GVL.stPMCtoPLC.Q500_01 AND NOT GVL.stPMCtoPLC.I501_01,
    PT := T#5s,
    ET => Cycle_Dpr_Cl_TON_ET); // TON
stILK.Alarm108 := Cycle_Dpr_Op_TON.Q OR Cycle_Dpr_Cl_TON.Q;

// NETWORK 109
// LSC1 tank level HH
LSC_HH_TON(IN := GVL.stPLCtoPMC.LSC1_Level_HH, PT := T#2s, ET => LSC_HH_TON_ET); // TON
stILK.Alarm109 := LSC_HH_TON.Q;

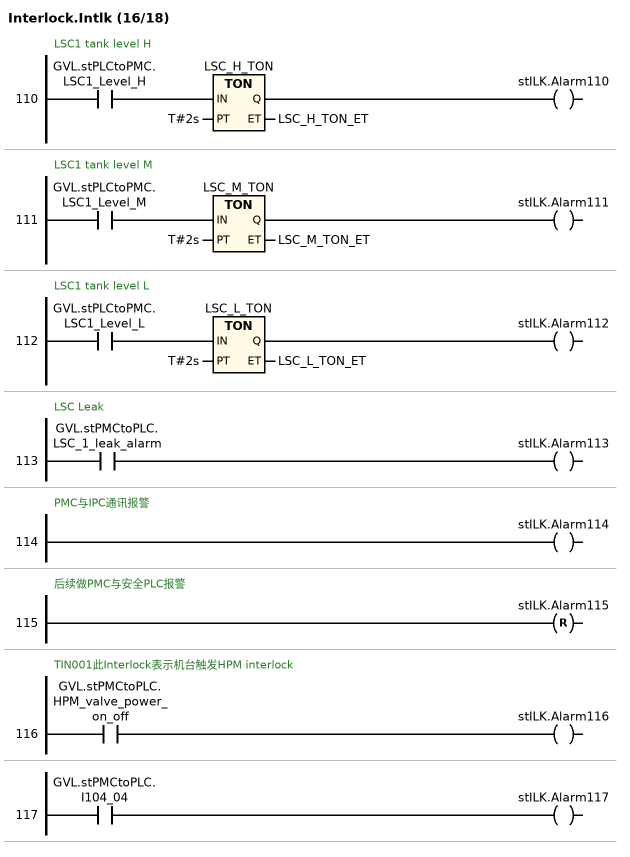
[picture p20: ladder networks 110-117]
// NETWORK 110
// LSC1 tank level H
LSC_H_TON(IN := GVL.stPLCtoPMC.LSC1_Level_H, PT := T#2s, ET => LSC_H_TON_ET); // TON
stILK.Alarm110 := LSC_H_TON.Q;

// NETWORK 111
// LSC1 tank level M
LSC_M_TON(IN := GVL.stPLCtoPMC.LSC1_Level_M, PT := T#2s, ET => LSC_M_TON_ET); // TON
stILK.Alarm111 := LSC_M_TON.Q;

// NETWORK 112
// LSC1 tank level L
LSC_L_TON(IN := GVL.stPLCtoPMC.LSC1_Level_L, PT := T#2s, ET => LSC_L_TON_ET); // TON
stILK.Alarm112 := LSC_L_TON.Q;

// NETWORK 113
// LSC Leak
stILK.Alarm113 := GVL.stPMCtoPLC.LSC_1_leak_alarm;

// NETWORK 114
// PMC与IPC通讯报警
stILK.Alarm114 := TRUE;

// NETWORK 115
// 后续做PMC与安全PLC报警
stILK.Alarm115 R= TRUE;

// NETWORK 116
// TIN001此Interlock表示机台触发HPM interlock
stILK.Alarm116 := GVL.stPMCtoPLC.HPM_valve_power_on_off;

// NETWORK 117
stILK.Alarm117 := GVL.stPMCtoPLC.I104_04;

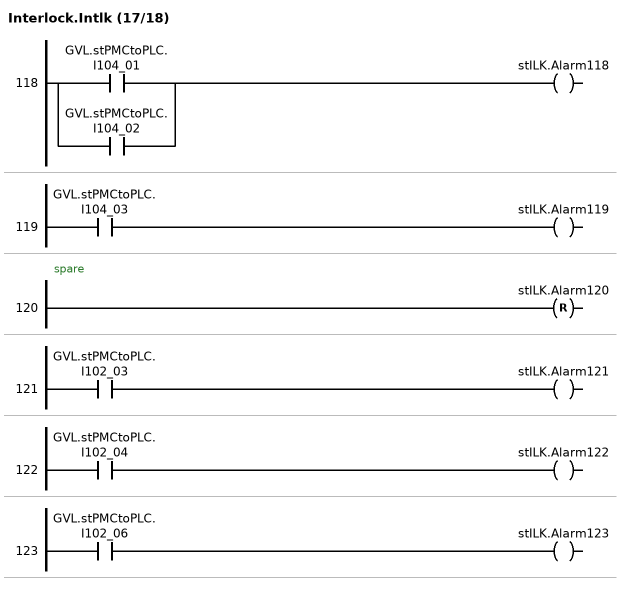
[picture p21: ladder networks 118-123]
// NETWORK 118
stILK.Alarm118 := GVL.stPMCtoPLC.I104_01 OR GVL.stPMCtoPLC.I104_02;

// NETWORK 119
stILK.Alarm119 := GVL.stPMCtoPLC.I104_03;

// NETWORK 120
// spare
stILK.Alarm120 R= TRUE;

// NETWORK 121
stILK.Alarm121 := GVL.stPMCtoPLC.I102_03;

// NETWORK 122
stILK.Alarm122 := GVL.stPMCtoPLC.I102_04;

// NETWORK 123
stILK.Alarm123 := GVL.stPMCtoPLC.I102_06;

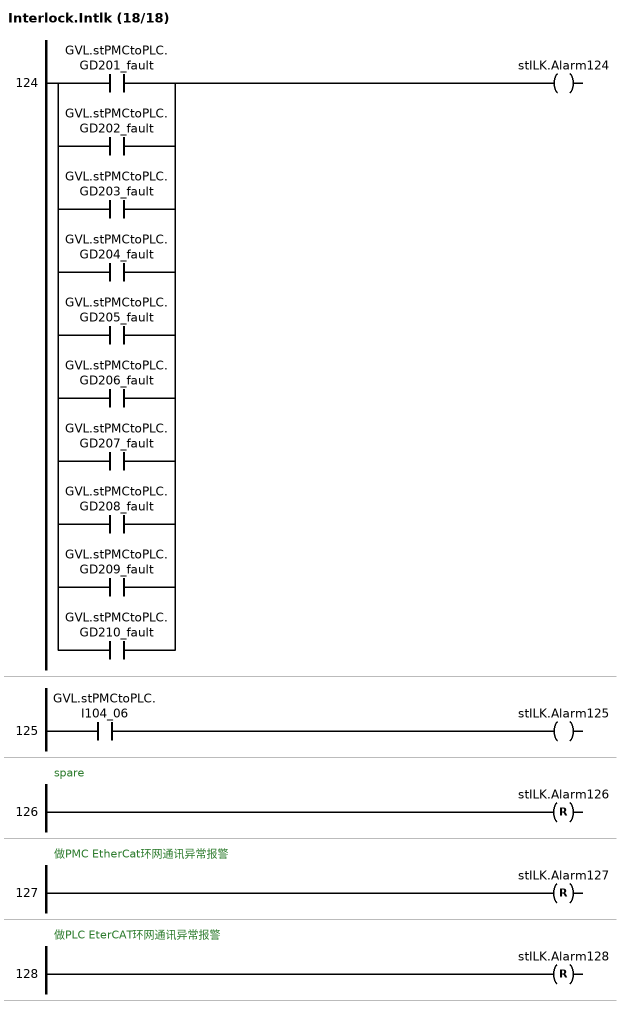
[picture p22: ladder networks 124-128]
// NETWORK 124
stILK.Alarm124 := GVL.stPMCtoPLC.GD201_fault OR GVL.stPMCtoPLC.GD202_fault OR GVL.stPMCtoPLC.GD203_fault OR GVL.stPMCtoPLC.GD204_fault OR GVL.stPMCtoPLC.GD205_fault OR GVL.stPMCtoPLC.GD206_fault OR GVL.stPMCtoPLC.GD207_fault OR GVL.stPMCtoPLC.GD208_fault OR GVL.stPMCtoPLC.GD209_fault OR GVL.stPMCtoPLC.GD210_fault;

// NETWORK 125
stILK.Alarm125 := GVL.stPMCtoPLC.I104_06;

// NETWORK 126
// spare
stILK.Alarm126 R= TRUE;

// NETWORK 127
// 做PMC EtherCat环网通讯异常报警
stILK.Alarm127 R= TRUE;

// NETWORK 128
// 做PLC EterCAT环网通讯异常报警
stILK.Alarm128 R= TRUE;
END_ACTION

ACTION VAC_Condition:
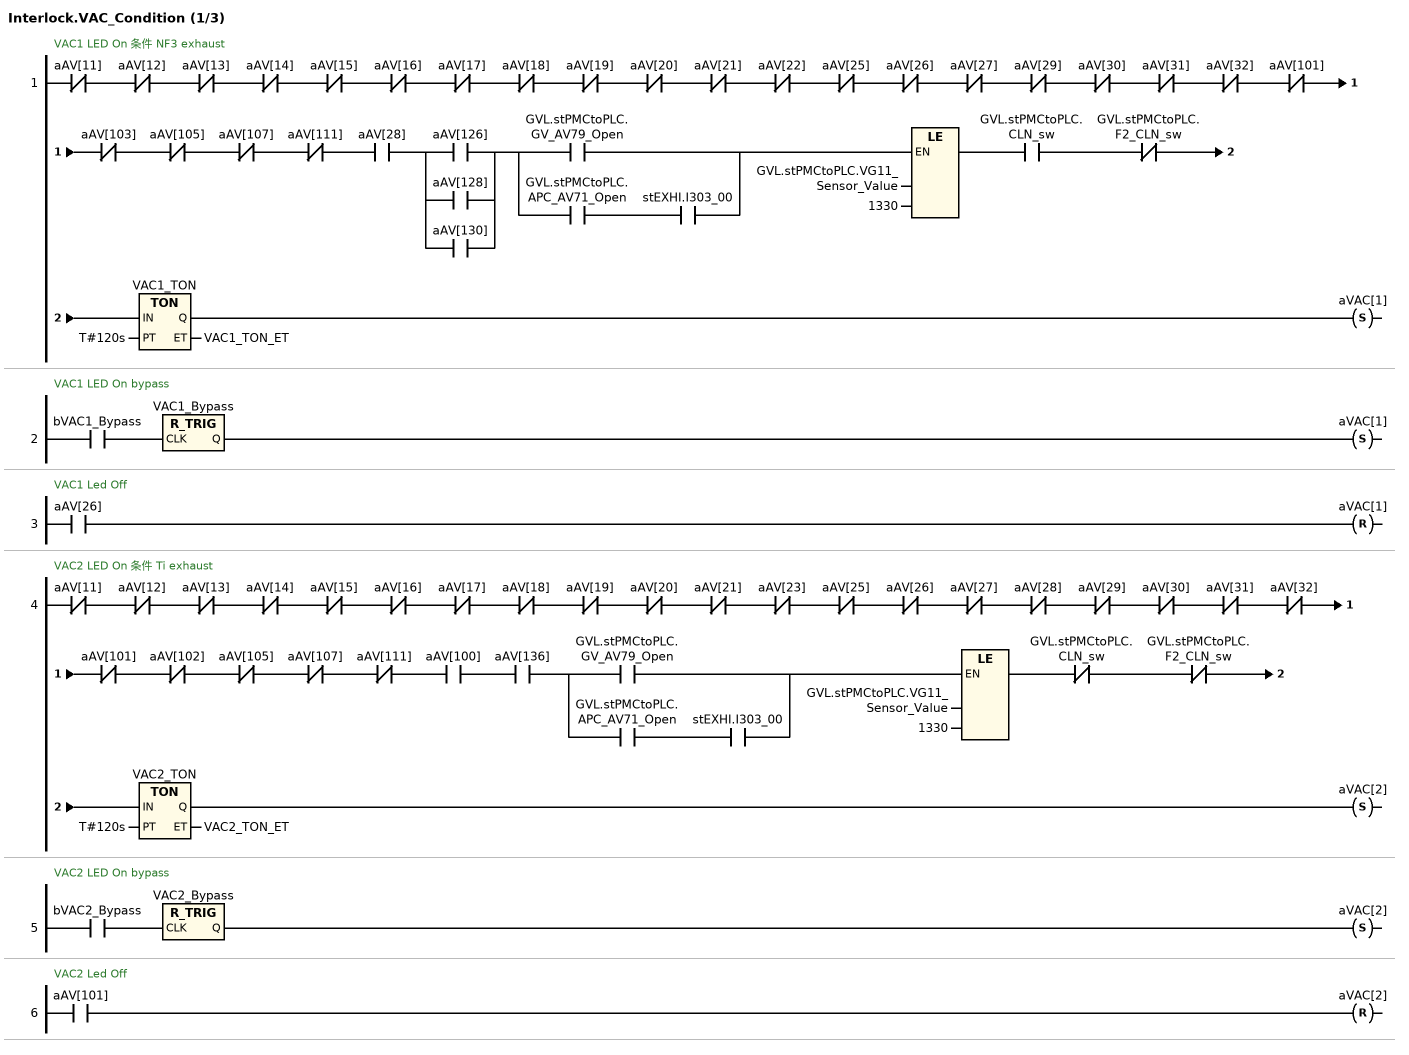
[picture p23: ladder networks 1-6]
// NETWORK 1
// VAC1 LED On 条件 NF3 exhaust
VAC1_TON(
    IN := (NOT aAV[11] AND NOT aAV[12] AND NOT aAV[13] AND NOT aAV[14] AND NOT aAV[15] AND NOT aAV[16] AND NOT aAV[17] AND NOT aAV[18] AND NOT aAV[19] AND NOT aAV[20] AND NOT aAV[21] AND NOT aAV[22] AND NOT aAV[25] AND NOT aAV[26] AND NOT aAV[27] AND NOT aAV[29] AND NOT aAV[30] AND NOT aAV[31] AND NOT aAV[32] AND NOT aAV[101] AND NOT aAV[103] AND NOT aAV[105] AND NOT aAV[107] AND NOT aAV[111] AND aAV[28] AND (aAV[126] OR aAV[128] OR aAV[130]) AND (GVL.stPMCtoPLC.GV_AV79_Open OR GVL.stPMCtoPLC.APC_AV71_Open AND stEXHI.I303_00) AND GVL.stPMCtoPLC.VG11_Sensor_Value <= 1330) AND GVL.stPMCtoPLC.CLN_sw AND NOT GVL.stPMCtoPLC.F2_CLN_sw,
    PT := T#120s,
    ET => VAC1_TON_ET); // TON
aVAC[1] S= VAC1_TON.Q;

// NETWORK 2
// VAC1 LED On bypass
VAC1_Bypass(CLK := bVAC1_Bypass); // R_TRIG
aVAC[1] S= VAC1_Bypass.Q;

// NETWORK 3
// VAC1 Led Off
aVAC[1] R= aAV[26];

// NETWORK 4
// VAC2 LED On 条件 Ti exhaust
VAC2_TON(
    IN := (NOT aAV[11] AND NOT aAV[12] AND NOT aAV[13] AND NOT aAV[14] AND NOT aAV[15] AND NOT aAV[16] AND NOT aAV[17] AND NOT aAV[18] AND NOT aAV[19] AND NOT aAV[20] AND NOT aAV[21] AND NOT aAV[23] AND NOT aAV[25] AND NOT aAV[26] AND NOT aAV[27] AND NOT aAV[28] AND NOT aAV[29] AND NOT aAV[30] AND NOT aAV[31] AND NOT aAV[32] AND NOT aAV[101] AND NOT aAV[102] AND NOT aAV[105] AND NOT aAV[107] AND NOT aAV[111] AND aAV[100] AND aAV[136] AND (GVL.stPMCtoPLC.GV_AV79_Open OR GVL.stPMCtoPLC.APC_AV71_Open AND stEXHI.I303_00) AND GVL.stPMCtoPLC.VG11_Sensor_Value <= 1330) AND NOT GVL.stPMCtoPLC.CLN_sw AND NOT GVL.stPMCtoPLC.F2_CLN_sw,
    PT := T#120s,
    ET => VAC2_TON_ET); // TON
aVAC[2] S= VAC2_TON.Q;

// NETWORK 5
// VAC2 LED On bypass
VAC2_Bypass(CLK := bVAC2_Bypass); // R_TRIG
aVAC[2] S= VAC2_Bypass.Q;

// NETWORK 6
// VAC2 Led Off
aVAC[2] R= aAV[101];

// NETWORK 7
// VAC3 LED On 条件 NH3 exhaust
VAC3_TON(
    IN := (NOT aAV[11] AND NOT aAV[12] AND NOT aAV[13] AND NOT aAV[15] AND NOT aAV[16] AND NOT aAV[17] AND NOT aAV[19] AND NOT aAV[20] AND NOT aAV[21] AND NOT aAV[22] AND NOT aAV[25] AND NOT aAV[26] AND NOT aAV[27] AND NOT aAV[29] AND NOT aAV[30] AND NOT aAV[31] AND NOT aAV[32] AND NOT aAV[101] AND NOT aAV[103] AND NOT aAV[105] AND NOT aAV[107] AND NOT aAV[111] AND aAV[14] AND aAV[120] AND aAV[121] AND aAV[124] AND (aAV[118] OR aAV[122] OR aAV[123] OR aAV[124]) AND (GVL.stPMCtoPLC.GV_AV79_Open OR GVL.stPMCtoPLC.APC_AV71_Open AND stEXHI.I303_00) AND GVL.stPMCtoPLC.VG11_Sensor_Value <= 1330) AND NOT GVL.stPMCtoPLC.CLN_sw AND NOT GVL.stPMCtoPLC.F2_CLN_sw,
    PT := T#120s,
    ET => VAC3_TON_ET); // TON
aVAC[3] S= VAC3_TON.Q;

// NETWORK 8
// VAC3 LED On bypass
VAC3_Bypass(CLK := bVAC3_Bypass); // R_TRIG
aVAC[3] S= VAC3_Bypass.Q;

// NETWORK 9
// VAC3 Led Off
aVAC[3] R= aAV[12] AND aAV[16];

// NETWORK 10
// VAC4 LED On 条件 SiH4 exhaust
VAC4_TON(
    IN := (NOT aAV[11] AND NOT aAV[12] AND NOT aAV[13] AND NOT aAV[14] AND NOT aAV[15] AND NOT aAV[16] AND NOT aAV[17] AND NOT aAV[18] AND NOT aAV[19] AND NOT aAV[20] AND NOT aAV[21] AND NOT aAV[25] AND NOT aAV[26] AND NOT aAV[27] AND NOT aAV[28] AND NOT aAV[29] AND NOT aAV[30] AND NOT aAV[31] AND NOT aAV[32] AND NOT aAV[101] AND NOT aAV[103] AND NOT aAV[105] AND NOT aAV[107] AND NOT aAV[111] AND aAV[22] AND aAV[131] AND (GVL.stPMCtoPLC.GV_AV79_Open OR GVL.stPMCtoPLC.APC_AV71_Open AND stEXHI.I303_00) AND GVL.stPMCtoPLC.VG11_Sensor_Value <= 1330) AND NOT GVL.stPMCtoPLC.CLN_sw AND NOT GVL.stPMCtoPLC.F2_CLN_sw,
    PT := T#120s,
    ET => VAC4_TON_ET); // TON
aVAC[4] S= VAC4_TON.Q;

// NETWORK 11
// VAC4 LED On bypass
VAC4_Bypass(CLK := bVAC4_Bypass); // R_TRIG
aVAC[4] S= VAC4_Bypass.Q;

// NETWORK 12
// VAC4 Led Off
aVAC[4] R= aAV[20];

// NETWORK 13
// VAC5 LED On 条件 F2 exhaust
VAC5_TON(
    IN := (NOT aAV[11] AND NOT aAV[12] AND NOT aAV[13] AND NOT aAV[14] AND NOT aAV[15] AND NOT aAV[16] AND NOT aAV[17] AND NOT aAV[18] AND NOT aAV[19] AND NOT aAV[20] AND NOT aAV[21] AND NOT aAV[22] AND NOT aAV[25] AND NOT aAV[26] AND NOT aAV[27] AND NOT aAV[28] AND NOT aAV[29] AND NOT aAV[30] AND NOT aAV[31] AND NOT aAV[101] AND NOT aAV[103] AND NOT aAV[105] AND NOT aAV[107] AND NOT aAV[111] AND aAV[32] AND (aAV[126] OR aAV[128] OR aAV[130]) AND (GVL.stPMCtoPLC.GV_AV79_Open OR GVL.stPMCtoPLC.APC_AV71_Open AND stEXHI.I303_00) AND GVL.stPMCtoPLC.VG11_Sensor_Value <= 1330) AND NOT GVL.stPMCtoPLC.CLN_sw AND GVL.stPMCtoPLC.F2_CLN_sw,
    PT := T#120s,
    ET => VAC5_TON_ET); // TON
aVAC[5] S= VAC5_TON.Q;

// NETWORK 14
// VAC5 LED On bypass
VAC5_Bypass(CLK := bVAC5_Bypass); // R_TRIG
aVAC[5] S= VAC5_Bypass.Q;

// NETWORK 15
// VAC5 Led Off
aVAC[5] R= aAV[30];
END_ACTION

ACTION Valve_Intlk:
// NETWORK 1
aILK_AV[1] := TRUE;

// NETWORK 2
// TIN001没有AV2
aILK_AV[2] := TRUE;

// NETWORK 3
aILK_AV[3] := (aAV[120] AND aAV[121] AND aAV[124] OR NOT aAV[14]) AND GVL.stPMCtoPLC.VG11_Sensor_Value <= 108000;

// NETWORK 4
aILK_AV[4] := aAV[125] AND GVL.stPMCtoPLC.VG11_Sensor_Value <= 108000;

// NETWORK 5
aILK_AV[5] := aAV[127] AND GVL.stPMCtoPLC.VG11_Sensor_Value <= 108000;

// NETWORK 6
aILK_AV[6] := aAV[129] AND GVL.stPMCtoPLC.VG11_Sensor_Value <= 108000;

// NETWORK 7
aILK_AV[7] := (aAV[122] AND aAV[123] AND aAV[124] OR NOT aAV[18]) AND GVL.stPMCtoPLC.VG11_Sensor_Value <= 108000;

// NETWORK 8
aILK_AV[8] := aAV[52] AND GVL.stPMCtoPLC.VG11_Sensor_Value <= 108000;

// NETWORK 9
aILK_AV[9] := (aAV[131] OR NOT aAV[22]) AND GVL.stPMCtoPLC.VG11_Sensor_Value <= 108000;

// NETWORK 10
// TIN001 没有AV10
aILK_AV[10] := TRUE;

// NETWORK 11
aILK_AV[11] := NOT aAV[12];

// NETWORK 12
aILK_AV[12] := (((NOT aAV[11] AND NOT aAV[17] AND NOT aAV[21] AND NOT aAV[26] AND NOT aAV[30] AND GVL.stPLCtoPMC.PG22_Pressure <= 150) AND GVL.stPMCtoPLC.I103_00 AND GVL.stPMCtoPLC.AGV_SW AND GVL.stPMCtoPLC.VG11_Sensor_Value < 1995) AND GVL.stPMCtoPLC.Boat_at_cap_position AND GVL.stPMCtoPLC.VG11_Sensor_Value <= 5320) AND GVL.stPMCtoPLC.HTR1_SW AND GVL.stPMCtoPLC.HTR2_SW AND GVL.stPMCtoPLC.HTR3_SW AND GVL.stPMCtoPLC.HTR4_SW AND GVL.stPMCtoPLC.HTR5_SW AND GVL.stPMCtoPLC.DEPO_SW AND NOT GVL.stPMCtoPLC.CLN_SW AND NOT GVL.stPMCtoPLC.F2_CLN_SW AND GVL.stPLCtoPMC.DEPO_OK AND aVAC[1] AND aVAC[5] AND GVL.stPMCtoPLC.HPM_valve_power_on_off AND NOT stILK.Alarm22 AND NOT stILK.Alarm27 AND NOT stILK.Alarm51 AND NOT stILK.Alarm52 AND NOT stILK.Alarm53 AND NOT stILK.Alarm61 AND NOT stILK.Alarm62 AND NOT stILK.Alarm80 AND NOT stILK.Alarm91 AND NOT stILK.Alarm109 AND NOT stILK.Alarm113 AND NOT stILK.Alarm116 AND NOT stILK.Alarm117;

// NETWORK 13
aILK_AV[13] := NOT aAV[14] AND NOT aAV[16] AND NOT aAV[20] AND GVL.stPMCtoPLC.I103_00 AND GVL.stPMCtoPLC.AGV_SW;

// NETWORK 14
_w5 := NOT aAV[13];
aILK_AV[14] := ((_w5 AND aAV[120]) AND aAV[121] AND aAV[124] OR _w5 AND NOT aAV[3]) AND GVL.stPMCtoPLC.VG11_Sensor_Value <= 1999.8;

// NETWORK 15
aILK_AV[15] := NOT aAV[16];

// NETWORK 16
_w6 := (NOT aAV[13] AND NOT aAV[15] AND NOT aAV[21] AND NOT aAV[26] AND NOT aAV[30] AND GVL.stPLCtoPMC.PG23_Pressure <= 150) AND GVL.stPMCtoPLC.I103_00 AND GVL.stPMCtoPLC.AGV_SW AND GVL.stPMCtoPLC.VG11_Sensor_Value < 1995;
aILK_AV[16] := (_w6 AND GVL.stPMCtoPLC.I501_07 AND GVL.stPMCtoPLC.VG11_Sensor_Value <= 5320 OR _w6 AND GVL.stPMCtoPLC.Boat_at_cap_position AND GVL.stPMCtoPLC.VG11_Sensor_Value <= 5320) AND GVL.stPMCtoPLC.HTR1_SW AND GVL.stPMCtoPLC.HTR2_SW AND GVL.stPMCtoPLC.HTR3_SW AND GVL.stPMCtoPLC.HTR4_SW AND GVL.stPMCtoPLC.HTR5_SW AND GVL.stPMCtoPLC.DEPO_SW AND NOT GVL.stPMCtoPLC.CLN_SW AND NOT GVL.stPMCtoPLC.F2_CLN_SW AND GVL.stPLCtoPMC.DEPO_OK AND aVAC[1] AND aVAC[5] AND GVL.stPMCtoPLC.HPM_valve_power_on_off AND NOT stILK.Alarm22 AND NOT stILK.Alarm27 AND NOT stILK.Alarm51 AND NOT stILK.Alarm52 AND NOT stILK.Alarm53 AND NOT stILK.Alarm61 AND NOT stILK.Alarm62 AND NOT stILK.Alarm80 AND NOT stILK.Alarm91 AND NOT stILK.Alarm109 AND NOT stILK.Alarm113 AND NOT stILK.Alarm116 AND NOT stILK.Alarm117;

// NETWORK 17
aILK_AV[17] := NOT aAV[12] AND NOT aAV[18] AND NOT aAV[20] AND GVL.stPMCtoPLC.I103_00 AND GVL.stPMCtoPLC.AGV_SW;

// NETWORK 18
_w7 := NOT aAV[17];
aILK_AV[18] := ((_w7 AND aAV[122]) AND aAV[123] AND aAV[124] OR _w7 AND NOT aAV[7]) AND GVL.stPMCtoPLC.VG11_Sensor_Value <= 1999.8;

// NETWORK 19
aILK_AV[19] := NOT aAV[20];

// NETWORK 20
_w8 := NOT aAV[13] AND NOT aAV[17] AND NOT aAV[19] AND NOT aAV[26] AND NOT aAV[30];
_w9 := _w8 AND GVL.stPMCtoPLC.VG11_Sensor_Value < 1330 OR _w8 AND aAV[75] AND GVL.stPMCtoPLC.VG13_Sensor_Value <= 1330;
aILK_AV[20] := (_w9 AND GVL.stPMCtoPLC.I501_07 AND GVL.stPMCtoPLC.VG11_Sensor_Value <= 5320 OR _w9 AND GVL.stPMCtoPLC.Boat_at_cap_position AND GVL.stPMCtoPLC.VG11_Sensor_Value <= 5320) AND GVL.stPMCtoPLC.I103_00 AND GVL.stPMCtoPLC.AGV_SW AND GVL.stPMCtoPLC.HTR1_SW AND GVL.stPMCtoPLC.HTR2_SW AND GVL.stPMCtoPLC.HTR3_SW AND GVL.stPMCtoPLC.HTR4_SW AND GVL.stPMCtoPLC.HTR5_SW AND GVL.stPMCtoPLC.DEPO_SW AND NOT GVL.stPMCtoPLC.CLN_SW AND NOT GVL.stPMCtoPLC.F2_CLN_SW AND GVL.stPLCtoPMC.DEPO_OK AND aVAC[1] AND aVAC[5] AND GVL.stPMCtoPLC.HPM_valve_power_on_off AND NOT stILK.Alarm22 AND NOT stILK.Alarm27 AND NOT stILK.Alarm51 AND NOT stILK.Alarm52 AND NOT stILK.Alarm53 AND NOT stILK.Alarm61 AND NOT stILK.Alarm62 AND NOT stILK.Alarm80 AND NOT stILK.Alarm91 AND NOT stILK.Alarm109 AND NOT stILK.Alarm113 AND NOT stILK.Alarm116 AND NOT stILK.Alarm117;

// NETWORK 21
aILK_AV[21] := NOT aAV[12] AND NOT aAV[16] AND NOT aAV[22] AND GVL.stPMCtoPLC.I103_00 AND GVL.stPMCtoPLC.AGV_SW;

// NETWORK 22
_w10 := NOT aAV[21] AND NOT aAV[124] AND aAV[131];
aILK_AV[22] := _w10 AND GVL.stPMCtoPLC.VG11_Sensor_Value <= 1330 OR _w10 AND aAV[75] AND GVL.stPMCtoPLC.VG13_Sensor_Value < 1330;

// NETWORK 23
aILK_AV[23] := TRUE;

// NETWORK 24
aILK_AV[24] := aAV[126] OR aAV[128] OR aAV[130] OR aAV[28] AND aAV[32];

// NETWORK 25
aILK_AV[25] := aAV[26];

// NETWORK 26
_w11 := NOT aAV[12] AND NOT aAV[16] AND NOT aAV[20] AND NOT aAV[25] AND NOT aAV[30] AND NOT aAV[101] AND GVL.stPMCtoPLC.VG11_Sensor_Value < 26600;
aILK_AV[26] := (_w11 AND GVL.stPMCtoPLC.I501_07 AND GVL.stPMCtoPLC.VG11_Sensor_Value <= 5320 OR _w11 AND GVL.stPMCtoPLC.Boat_at_cap_position AND GVL.stPMCtoPLC.VG11_Sensor_Value <= 5320) AND GVL.stPMCtoPLC.I103_00 AND GVL.stPMCtoPLC.AGV_SW AND GVL.stPMCtoPLC.HTR1_SW AND GVL.stPMCtoPLC.HTR2_SW AND NOT GVL.stPMCtoPLC.HTR3_SW AND GVL.stPMCtoPLC.HTR4_SW AND GVL.stPMCtoPLC.HTR5_SW AND NOT GVL.stPMCtoPLC.DEPO_SW AND GVL.stPMCtoPLC.CLN_SW AND NOT GVL.stPMCtoPLC.F2_CLN_SW AND aVAC[2] AND aVAC[3] AND aVAC[4] AND aVAC[5] AND GVL.stPMCtoPLC.HPM_valve_power_on_off AND NOT stILK.Alarm22 AND NOT stILK.Alarm27 AND NOT stILK.Alarm51 AND NOT stILK.Alarm52 AND NOT stILK.Alarm53 AND NOT stILK.Alarm61 AND NOT stILK.Alarm62 AND NOT stILK.Alarm80 AND NOT stILK.Alarm91 AND NOT stILK.Alarm109 AND NOT stILK.Alarm113 AND NOT stILK.Alarm116 AND NOT stILK.Alarm117;

// NETWORK 27
aILK_AV[27] := NOT aAV[28] AND (NOT aAV[31] OR NOT aAV[30] AND aVAC[5]) AND GVL.stPMCtoPLC.I103_00 AND GVL.stPMCtoPLC.AGV_SW;

// NETWORK 28
aILK_AV[28] := NOT aAV[27] AND NOT aAV[32] AND (aAV[126] OR aAV[128] OR aAV[130]) AND GVL.stPMCtoPLC.VG11_Sensor_Value < 26600;

// NETWORK 29
aILK_AV[29] := NOT aAV[30];

// NETWORK 30
_w12 := (NOT aAV[12] AND NOT aAV[16] AND NOT aAV[20] AND NOT aAV[26] AND NOT aAV[29] AND aAV[101] AND GVL.stPMCtoPLC.VG11_Sensor_Value < 39900) AND NOT stILK.Alarm105;
aILK_AV[30] := (_w12 AND GVL.stPMCtoPLC.I501_07 AND GVL.stPMCtoPLC.VG11_Sensor_Value <= 5320 OR _w12 AND GVL.stPMCtoPLC.Boat_at_cap_position AND GVL.stPMCtoPLC.VG11_Sensor_Value <= 5320) AND GVL.stPMCtoPLC.I103_00 AND GVL.stPMCtoPLC.AGV_SW AND GVL.stPMCtoPLC.HTR1_SW AND GVL.stPMCtoPLC.HTR2_SW AND NOT GVL.stPMCtoPLC.HTR3_SW AND GVL.stPMCtoPLC.HTR4_SW AND GVL.stPMCtoPLC.HTR5_SW AND NOT GVL.stPMCtoPLC.DEPO_SW AND NOT GVL.stPMCtoPLC.CLN_SW AND GVL.stPMCtoPLC.F2_CLN_SW AND aVAC[1] AND aVAC[2] AND aVAC[3] AND aVAC[4] AND GVL.stPMCtoPLC.HPM_valve_power_on_off AND NOT stILK.Alarm22 AND NOT stILK.alarm27 AND NOT stILK.alarm51 AND NOT stILK.alarm52 AND NOT stILK.alarm53 AND NOT stILK.alarm61 AND NOT stILK.alarm62 AND NOT stILK.alarm80 AND NOT stILK.alarm91 AND NOT stILK.alarm109 AND NOT stILK.alarm113 AND NOT stILK.alarm116 AND NOT stILK.alarm117;

// NETWORK 31
aILK_AV[31] := NOT aAV[32] AND (NOT aAV[27] OR NOT aAV[26] AND aVAC[1]) AND GVL.stPMCtoPLC.I103_00 AND GVL.stPMCtoPLC.AGV_SW;

// NETWORK 32
aILK_AV[32] := NOT aAV[28] AND NOT aAV[31] AND (aAV[126] OR aAV[128] OR aAV[130]) AND GVL.stPMCtoPLC.VG11_Sensor_Value < 39900;

// NETWORK 33
aILK_AV[33] := TRUE;

// NETWORK 34
aILK_AV[34] := TRUE;

// NETWORK 35
aILK_AV[35] := TRUE;

// NETWORK 36
aILK_AV[36] := TRUE;

// NETWORK 37
aILK_AV[37] := TRUE;

// NETWORK 38
aILK_AV[38] := TRUE;

// NETWORK 39
aILK_AV[39] := TRUE;

// NETWORK 40
aILK_AV[40] := TRUE;

// NETWORK 41
aILK_AV[41] := TRUE;

// NETWORK 42
aILK_AV[42] := TRUE;

// NETWORK 43
aILK_AV[43] := TRUE;

// NETWORK 44
aILK_AV[44] := TRUE;

// NETWORK 45
aILK_AV[45] := TRUE;

// NETWORK 46
aILK_AV[46] := TRUE;

// NETWORK 47
aILK_AV[47] := TRUE;

// NETWORK 48
aILK_AV[48] := TRUE;

// NETWORK 49
aILK_AV[49] := TRUE;

// NETWORK 50
aILK_AV[50] := TRUE;

// NETWORK 51
aILK_AV[51] := TRUE;

// NETWORK 52
// 无条件开关
aILK_AV[52] := TRUE;

// NETWORK 53
aILK_AV[53] := TRUE;

// NETWORK 54 (disabled)
// aILK_AV[54] := TRUE;

// NETWORK 55
aILK_AV[55] := TRUE;

// NETWORK 56
aILK_AV[56] := TRUE;

// NETWORK 57
aILK_AV[57] := TRUE;

// NETWORK 58
aILK_AV[58] := TRUE;

// NETWORK 59
aILK_AV[59] := TRUE;

// NETWORK 60 (disabled)
// aILK_AV[60] := TRUE;

// NETWORK 61
aILK_AV[61] := TRUE;

// NETWORK 62
aILK_AV[62] := TRUE;

// NETWORK 63
aILK_AV[63] := TRUE;

// NETWORK 64
aILK_AV[64] := TRUE;

// NETWORK 65
aILK_AV[65] := NOT bFFUAlarm;

// NETWORK 66
aILK_AV[66] := TRUE;

// NETWORK 67
// AV67 DG1 Protect
aILK_AV[67] := aVAC[1] AND aVAC[2] AND aVAC[3] AND aVAC[4] AND aVAC[5];

// NETWORK 68 (disabled)
// aILK_AV[68] := TRUE;

// NETWORK 69
aILK_AV[69] := TRUE;

// NETWORK 70
aILK_AV[70] := TRUE;

// NETWORK 71
_w13 := GVL.stPMCtoPLC.I103_00 AND GVL.stPMCtoPLC.AGV_SW;
_w14 := _w13 AND GVL.stPMCtoPLC.I501_07 OR _w13 AND GVL.stPMCtoPLC.Boat_at_cap_position OR _w13 AND GVL.stPMCtoPLC.Boat_at_cap_position AND GVL.stPMCtoPLC.VG11_Sensor_Value <= 5320;
aILK_AV[71] := _w14 AND NOT GVL.stPMCtoPLC.Boat_at_cap_position OR _w14 AND aAV[52] OR _w14 AND GVL.stPMCtoPLC.VG11_Sensor_Value <= 1995;

// NETWORK 72
aILK_AV[72] := GVL.stPMCtoPLC.I103_00;

// NETWORK 73 (disabled)
// aILK_AV[73] := TRUE;

// NETWORK 74 (disabled)
// aILK_AV[74] := TRUE;

// NETWORK 75
aILK_AV[75] := GVL.stPMCtoPLC.VG11_Sensor_Value <= 1995 AND GVL.stPMCtoPLC.I103_00;

// NETWORK 76
aILK_AV[76] := TRUE;

// NETWORK 77 (disabled)
// aILK_AV[77] := TRUE;

// NETWORK 78
aILK_AV[78] := TRUE;

// NETWORK 79
aILK_AV[79] := ((GVL.stPMCtoPLC.Boat_at_cap_position OR GVL.stPMCtoPLC.I501_07) AND GVL.stPMCtoPLC.VG11_Sensor_Value <= 1995) AND GVL.stPMCtoPLC.I103_00 AND NOT stILK.Alarm12 AND NOT stILK.Alarm98 AND (NOT GVL.stPMCtoPLC.Boat_at_cap_position OR aAV[52]);

// NETWORK 80
aILK_AV[80] := TRUE;

// NETWORK 81
aILK_AV[81] := TRUE;

// NETWORK 82
aILK_AV[82] := TRUE;

// NETWORK 83
aILK_AV[83] := TRUE;

// NETWORK 84
aILK_AV[84] := TRUE;

// NETWORK 85
// AV85 BG1
aILK_AV[85] := GVL.stPMCtoPLC.I103_00 AND NOT stILK.Alarm40;

// NETWORK 86
// AV86 BG1
aILK_AV[86] := GVL.stPMCtoPLC.I103_00 AND NOT stILK.Alarm40;

// NETWORK 87
// AV87 BG1
aILK_AV[87] := GVL.stPMCtoPLC.I103_00 AND NOT stILK.Alarm40;

// NETWORK 88
// AV88 BG1
aILK_AV[88] := GVL.stPMCtoPLC.I103_00 AND NOT stILK.Alarm40;

// NETWORK 89
aILK_AV[89] := TRUE;

// NETWORK 90
aILK_AV[90] := TRUE;

// NETWORK 91
aILK_AV[91] := TRUE;

// NETWORK 92
aILK_AV[92] := TRUE;

// NETWORK 93
aILK_AV[93] := TRUE;

// NETWORK 94
aILK_AV[94] := TRUE;

// NETWORK 95
aILK_AV[95] := TRUE;

// NETWORK 96
aILK_AV[96] := TRUE;

// NETWORK 97
aILK_AV[97] := TRUE;

// NETWORK 98
aILK_AV[98] := TRUE;

// NETWORK 99
aILK_AV[99] := TRUE;

// NETWORK 100 (disabled)
// aILK_AV[100] := TRUE;

// NETWORK 101
_w15 := (NOT aAV[26] AND NOT aAV[30] AND NOT aAV[100] AND NOT aAV[102] AND GVL.stPMCtoPLC.HTR1_SW AND GVL.stPMCtoPLC.HTR2_SW AND GVL.stPMCtoPLC.HTR3_SW AND GVL.stPMCtoPLC.HTR4_SW AND GVL.stPMCtoPLC.HTR5_SW AND GVL.stPMCtoPLC.DEPO_SW AND NOT GVL.stPMCtoPLC.CLN_SW AND NOT GVL.stPMCtoPLC.F2_CLN_SW AND GVL.stPLCtoPMC.DEPO_OK AND GVL.stPMCtoPLC.I103_00 AND GVL.stPMCtoPLC.AGV_SW AND GVL.stPMCtoPLC.VG11_Sensor_Value < 39900) AND NOT stILK.Alarm26;
aILK_AV[101] := (_w15 AND GVL.stPMCtoPLC.I501_07 AND GVL.stPMCtoPLC.VG11_Sensor_Value <= 5320 OR _w15 AND GVL.stPMCtoPLC.Boat_at_cap_position AND GVL.stPMCtoPLC.VG11_Sensor_Value <= 5320) AND aVAC[1] AND aVAC[5] AND GVL.stPMCtoPLC.HPM_valve_power_on_off AND NOT stILK.Alarm22 AND NOT stILK.alarm27 AND NOT stILK.Alarm51 AND NOT stILK.alarm52 AND NOT stILK.alarm53 AND NOT stILK.alarm61 AND NOT stILK.alarm62 AND NOT stILK.alarm80 AND NOT stILK.Alarm91 AND NOT stILK.Alarm109 AND NOT stILK.Alarm113 AND NOT stILK.Alarm116 AND NOT stILK.Alarm117;

// NETWORK 102
aILK_AV[102] := NOT aAV[101] AND NOT aAV[112] AND NOT stILK.Alarm26 AND NOT stILK.Alarm113;

// NETWORK 103
_w16 := NOT aAV[105];
_w17 := _w16 AND aAV[137];
IF NOT _w17 THEN
    _w17 := _w16 AND GVL.stPMCtoPLC.VG11_Sensor_Value <= 1995;
END_IF
aILK_AV[103] := _w17 AND NOT stILK.Alarm26 AND GVL.stPLCtoPMC.PS33_Pressure <= 200;

// NETWORK 104
aILK_AV[104] := TRUE;

// NETWORK 105
aILK_AV[105] := NOT aAV[103] AND GVL.stPMCtoPLC.VG11_Sensor_Value <= 108000;

// NETWORK 106
aILK_AV[106] := NOT aAV[100] AND NOT GVL.stPMCtoPLC.T_REF_sw;

// NETWORK 107
aILK_AV[107] := NOT aAV[137] AND GVL.stPMCtoPLC.I103_00 AND GVL.stPMCtoPLC.AGV_SW;

// NETWORK 108
aILK_AV[108] := TRUE;

// NETWORK 109
aILK_AV[109] := TRUE;

// NETWORK 110
// VG31 protect
aILK_AV[110] := TRUE;

// NETWORK 111
aILK_AV[111] := NOT aAV[112] AND GVL.stPMCtoPLC.T_REF_sw AND NOT stILK.Alarm121 OR GVL.stPMCtoPLC.T_MNT_sw AND GVL.stPMCtoPLC.T_REF_sw;

// NETWORK 112
aILK_AV[112] := NOT aAV[102] AND NOT stILK.Alarm111;

// NETWORK 113
aILK_AV[113] := TRUE;

// NETWORK 114
aILK_AV[114] := TRUE;

// NETWORK 115
aILK_AV[115] := TRUE;

// NETWORK 116
aILK_AV[116] := TRUE;

// NETWORK 117
aILK_AV[117] := TRUE;

// NETWORK 118
aILK_AV[118] := TRUE;

// NETWORK 119
aILK_AV[119] := TRUE;

// NETWORK 120
aILK_AV[120] := GVL.stPLCtoPMC.PG22_Pressure <= 200;

// NETWORK 121
aILK_AV[121] := ((NOT aAV[123] OR GVL.stPLCtoPMC.PG22_Pressure <= 20 OR NOT aAV[12] AND NOT aAV[14]) AND GVL.stPMCtoPLC.VG11_Sensor_Value <= 108000) AND aAV[124];

// NETWORK 122
aILK_AV[122] := GVL.stPLCtoPMC.PG23_Pressure <= 200;

// NETWORK 123
aILK_AV[123] := ((NOT aAV[121] OR GVL.stPLCtoPMC.PG23_Pressure <= 20 OR NOT aAV[16] AND NOT aAV[18]) AND GVL.stPMCtoPLC.VG11_Sensor_Value <= 108000) AND aAV[124];

// NETWORK 124
aILK_AV[124] := NOT aAV[22];

// NETWORK 125
aILK_AV[125] := TRUE;

// NETWORK 126
aILK_AV[126] := TRUE;

// NETWORK 127
aILK_AV[127] := TRUE;

// NETWORK 128
aILK_AV[128] := TRUE;

// NETWORK 129
aILK_AV[129] := TRUE;

// NETWORK 130
aILK_AV[130] := TRUE;

// NETWORK 131
aILK_AV[131] := TRUE;

// NETWORK 132
aILK_AV[132] := TRUE;

// NETWORK 133
aILK_AV[133] := TRUE;

// NETWORK 134
aILK_AV[134] := TRUE;

// NETWORK 135
aILK_AV[135] := TRUE;

// NETWORK 136
aILK_AV[136] := NOT aAV[137] AND GVL.stPMCtoPLC.Boat_at_cap_position AND GVL.stPMCtoPLC.I103_00 AND GVL.stPMCtoPLC.VG11_Sensor_Value <= 1995;

// NETWORK 137
aILK_AV[137] := NOT aAV[107] AND NOT aAV[136] AND GVL.stPMCtoPLC.I103_00 AND GVL.stPMCtoPLC.AGV_SW AND NOT stILK.Alarm40;

// NETWORK 138
aILK_AV[138] := TRUE;

// NETWORK 139
aILK_AV[139] := TRUE;

// NETWORK 140
aILK_AV[140] := TRUE;

// NETWORK 141
aILK_AV[141] := TRUE;

// NETWORK 142
aILK_AV[142] := TRUE;

// NETWORK 143
aILK_AV[143] := TRUE;

// NETWORK 144
aILK_AV[144] := TRUE;

// NETWORK 145
aILK_AV[145] := TRUE;

// NETWORK 146
aILK_AV[146] := TRUE;

// NETWORK 147
aILK_AV[147] := TRUE;

// NETWORK 148
aILK_AV[148] := TRUE;

// NETWORK 149
aILK_AV[149] := TRUE;

// NETWORK 150
aILK_AV[150] := TRUE;

// NETWORK 151
// Dry pump
GVL.stPLCtoPMC.DP := GVL.stPMCtoPLC.DP_sw AND GVL.stPMCtoPLC.I103_00;

// NETWORK 152
// Blower
GVL.stPLCtoPMC.BWR := GVL.stPMCtoPLC.BWR_sw AND NOT stILK.Alarm70 AND NOT stILK.Alarm72 AND (GVL.stPMCtoPLC.DPR1_sw OR GVL.stPMCtoPLC.DPR2_sw);

// NETWORK 153
// Damper-1
GVL.stPLCtoPMC.DPR1 := GVL.stPMCtoPLC.DPR1_sw AND NOT stILK.Alarm70 AND NOT stILK.Alarm72 AND NOT GVL.stPMCtoPLC.DPR2_sw;

// NETWORK 154
// Damper-2
GVL.stPLCtoPMC.DPR2 := GVL.stPMCtoPLC.DPR2_sw AND NOT stILK.Alarm70 AND NOT stILK.Alarm72 AND NOT GVL.stPMCtoPLC.DPR1_sw;

// NETWORK 155
// R-axis water
GVL.stPLCtoPMC.WAT_R := GVL.stPMCtoPLC.WAT_R_sw;

// NETWORK 156
// Flange water not using
GVL.stPLCtoPMC.WAT_F := GVL.stPMCtoPLC.WAT_F_sw;

// NETWORK 157
// HTR1 GAS
GVL.stPLCtoPMC.HTR1 := GVL.stPMCtoPLC.HTR1_SW;

// NETWORK 158
// HTR2 EXHAUST
GVL.stPLCtoPMC.HTR2 := GVL.stPMCtoPLC.HTR2_SW;

// NETWORK 159
// HTR3 HOT N2/Pump Heater
GVL.stPLCtoPMC.HTR3 := GVL.stPMCtoPLC.HTR3_SW AND NOT aAV[26] AND NOT aAV[30];

// NETWORK 160
// HTR4 LSC Heater
GVL.stPLCtoPMC.HTR4 := GVL.stPMCtoPLC.HTR4_SW;

// NETWORK 161
// HTR5 1`2F Pipe Heater
GVL.stPLCtoPMC.HTR5 := GVL.stPMCtoPLC.HTR5_SW;

// NETWORK 162
// T_REF
GVL.stPLCtoPMC.T_REF := GVL.stPMCtoPLC.T_REF_sw AND NOT aAV[106] AND NOT stILK.Alarm121 AND NOT stILK.Alarm123 AND NOT stILK.Alarm126 AND NOT stILK.Alarm116 AND GVL.stPMCtoPLC.I102_02 AND NOT stILK.Alarm113 AND (GVL.stPLCtoPMC.LSC1_Level_L OR GVL.stPLCtoPMC.LSC1_Level_M) AND NOT GVL.stPLCtoPMC.LSC1_Level_H AND NOT GVL.stPLCtoPMC.LSC1_Level_HH;

// NETWORK 163
// DEPO Select
GVL.stPLCtoPMC.DEPO := GVL.stPMCtoPLC.DEPO_SW AND NOT aAV[26] AND NOT aAV[30] AND NOT GVL.stPMCtoPLC.CLN_SW AND NOT GVL.stPMCtoPLC.F2_CLN_SW;

// NETWORK 164
// Cleaning Select
GVL.stPLCtoPMC.CLN := GVL.stPMCtoPLC.CLN_SW AND NOT aAV[12] AND NOT aAV[16] AND NOT aAV[20] AND NOT aAV[30] AND NOT aAV[101] AND NOT GVL.stPMCtoPLC.DEPO_SW AND NOT GVL.stPMCtoPLC.F2_CLN_SW;

// NETWORK 165
// Pump ECO mode
GVL.stPLCtoPMC.ECO := GVL.stPMCtoPLC.Pump1_ECO_sw AND NOT aAV[12] AND NOT aAV[16] AND NOT aAV[20] AND NOT aAV[30] AND NOT aAV[101];

// NETWORK 166
GVL.stPLCtoPMC.AGV := GVL.stPMCtoPLC.AGV_SW;

// NETWORK 167
// Spare ,NO Using
GVL.stPLCtoPMC.SP1 := TRUE;

// NETWORK 168
// PZ PS13 Auto Zero
GVL.stPLCtoPMC.PZ := GVL.stPMCtoPLC.PZ_sw AND NOT aAV[52] AND NOT aAV[67] AND NOT aAV[124] AND NOT aAV[125] AND NOT aAV[126] AND NOT aAV[127] AND NOT aAV[128] AND NOT aAV[129] AND NOT aAV[130] AND NOT aAV[131] AND NOT aAV[136] AND aAV[60];

// NETWORK 169
// Pressure control ,NO Using
GVL.stPLCtoPMC.P_CONT := GVL.stPMCtoPLC.P_CONT_sw;

// NETWORK 170
// DG1 zero adj,NO Using
GVL.stPLCtoPMC.DGZERO := GVL.stPMCtoPLC.DGZERO_sw;

// NETWORK 171
// 1 pass
GVL.stPLCtoPMC.C_EXH := GVL.stPMCtoPLC.C_EXH_sw;

// NETWORK 172
// F2 cleaning seclect
GVL.stPLCtoPMC.F2_CLN := GVL.stPMCtoPLC.F2_CLN_sw;

// NETWORK 173
// Foup N2 shut off
GVL.stPLCtoPMC.F_N := GVL.stPMCtoPLC.F_N_sw;
END_ACTION

END_PROGRAM
